VERSION 5.8 ;
BUSBITCHARS "[]" ;
DIVIDERCHAR "/" ;
UNITS
    DATABASE MICRONS 1000 ;
END UNITS

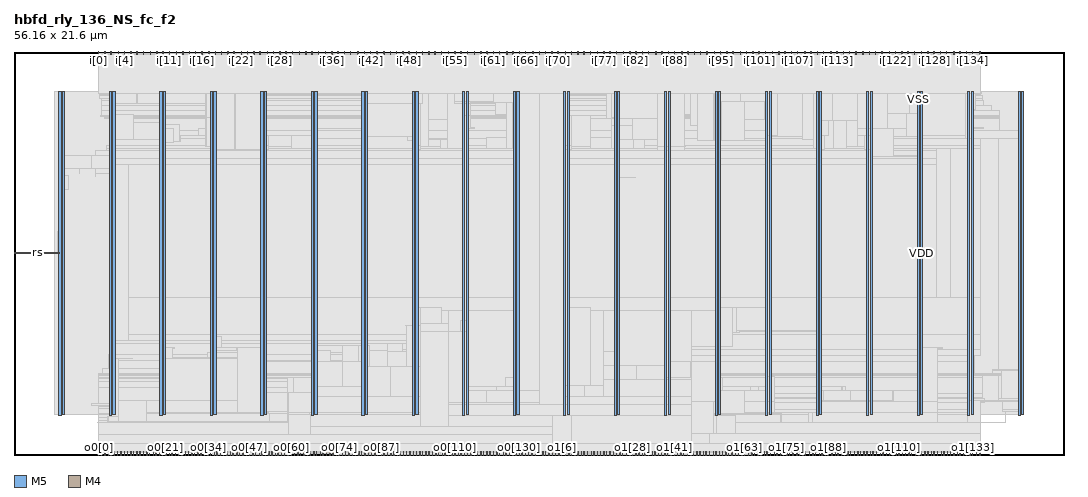
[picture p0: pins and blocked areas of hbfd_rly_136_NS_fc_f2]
MACRO hbfd_rly_136_NS_fc_f2
  FOREIGN hbfd_rly_136_NS_fc_f2 0 0 ;
  CLASS BLOCK ;
  SIZE 56.16 BY 21.6 ;
  PIN clk_in
    DIRECTION INPUT ;
    USE SIGNAL ;
    PORT
      LAYER M5 ;
        RECT  28.08 21.408 28.104 21.6 ;
    END
  END clk_in
  PIN clk_out0
    DIRECTION OUTPUT ;
    USE SIGNAL ;
    PORT
      LAYER M5 ;
        RECT  16.176 0 16.2 0.192 ;
    END
  END clk_out0
  PIN clk_out1
    DIRECTION OUTPUT ;
    USE SIGNAL ;
    PORT
      LAYER M5 ;
        RECT  39.936 0 39.96 0.192 ;
    END
  END clk_out1
  PIN i[0]
    DIRECTION INPUT ;
    USE SIGNAL ;
    PORT
      LAYER M5 ;
        RECT  4.512 21.408 4.536 21.6 ;
    END
  END i[0]
  PIN i[100]
    DIRECTION INPUT ;
    USE SIGNAL ;
    PORT
      LAYER M5 ;
        RECT  39.504 21.408 39.528 21.6 ;
    END
  END i[100]
  PIN i[101]
    DIRECTION INPUT ;
    USE SIGNAL ;
    PORT
      LAYER M5 ;
        RECT  39.84 21.408 39.864 21.6 ;
    END
  END i[101]
  PIN i[102]
    DIRECTION INPUT ;
    USE SIGNAL ;
    PORT
      LAYER M5 ;
        RECT  40.176 21.408 40.2 21.6 ;
    END
  END i[102]
  PIN i[103]
    DIRECTION INPUT ;
    USE SIGNAL ;
    PORT
      LAYER M5 ;
        RECT  40.56 21.408 40.584 21.6 ;
    END
  END i[103]
  PIN i[104]
    DIRECTION INPUT ;
    USE SIGNAL ;
    PORT
      LAYER M5 ;
        RECT  40.896 21.408 40.92 21.6 ;
    END
  END i[104]
  PIN i[105]
    DIRECTION INPUT ;
    USE SIGNAL ;
    PORT
      LAYER M5 ;
        RECT  41.232 21.408 41.256 21.6 ;
    END
  END i[105]
  PIN i[106]
    DIRECTION INPUT ;
    USE SIGNAL ;
    PORT
      LAYER M5 ;
        RECT  41.568 21.408 41.592 21.6 ;
    END
  END i[106]
  PIN i[107]
    DIRECTION INPUT ;
    USE SIGNAL ;
    PORT
      LAYER M5 ;
        RECT  41.904 21.408 41.928 21.6 ;
    END
  END i[107]
  PIN i[108]
    DIRECTION INPUT ;
    USE SIGNAL ;
    PORT
      LAYER M5 ;
        RECT  42.288 21.408 42.312 21.6 ;
    END
  END i[108]
  PIN i[109]
    DIRECTION INPUT ;
    USE SIGNAL ;
    PORT
      LAYER M5 ;
        RECT  42.624 21.408 42.648 21.6 ;
    END
  END i[109]
  PIN i[10]
    DIRECTION INPUT ;
    USE SIGNAL ;
    PORT
      LAYER M5 ;
        RECT  7.968 21.408 7.992 21.6 ;
    END
  END i[10]
  PIN i[110]
    DIRECTION INPUT ;
    USE SIGNAL ;
    PORT
      LAYER M5 ;
        RECT  42.96 21.408 42.984 21.6 ;
    END
  END i[110]
  PIN i[111]
    DIRECTION INPUT ;
    USE SIGNAL ;
    PORT
      LAYER M5 ;
        RECT  43.296 21.408 43.32 21.6 ;
    END
  END i[111]
  PIN i[112]
    DIRECTION INPUT ;
    USE SIGNAL ;
    PORT
      LAYER M5 ;
        RECT  43.68 21.408 43.704 21.6 ;
    END
  END i[112]
  PIN i[113]
    DIRECTION INPUT ;
    USE SIGNAL ;
    PORT
      LAYER M5 ;
        RECT  44.016 21.408 44.04 21.6 ;
    END
  END i[113]
  PIN i[114]
    DIRECTION INPUT ;
    USE SIGNAL ;
    PORT
      LAYER M5 ;
        RECT  44.352 21.408 44.376 21.6 ;
    END
  END i[114]
  PIN i[115]
    DIRECTION INPUT ;
    USE SIGNAL ;
    PORT
      LAYER M5 ;
        RECT  44.688 21.408 44.712 21.6 ;
    END
  END i[115]
  PIN i[116]
    DIRECTION INPUT ;
    USE SIGNAL ;
    PORT
      LAYER M5 ;
        RECT  45.024 21.408 45.048 21.6 ;
    END
  END i[116]
  PIN i[117]
    DIRECTION INPUT ;
    USE SIGNAL ;
    PORT
      LAYER M5 ;
        RECT  45.408 21.408 45.432 21.6 ;
    END
  END i[117]
  PIN i[118]
    DIRECTION INPUT ;
    USE SIGNAL ;
    PORT
      LAYER M5 ;
        RECT  45.744 21.408 45.768 21.6 ;
    END
  END i[118]
  PIN i[119]
    DIRECTION INPUT ;
    USE SIGNAL ;
    PORT
      LAYER M5 ;
        RECT  46.08 21.408 46.104 21.6 ;
    END
  END i[119]
  PIN i[11]
    DIRECTION INPUT ;
    USE SIGNAL ;
    PORT
      LAYER M5 ;
        RECT  8.304 21.408 8.328 21.6 ;
    END
  END i[11]
  PIN i[120]
    DIRECTION INPUT ;
    USE SIGNAL ;
    PORT
      LAYER M5 ;
        RECT  46.416 21.408 46.44 21.6 ;
    END
  END i[120]
  PIN i[121]
    DIRECTION INPUT ;
    USE SIGNAL ;
    PORT
      LAYER M5 ;
        RECT  46.8 21.408 46.824 21.6 ;
    END
  END i[121]
  PIN i[122]
    DIRECTION INPUT ;
    USE SIGNAL ;
    PORT
      LAYER M5 ;
        RECT  47.136 21.408 47.16 21.6 ;
    END
  END i[122]
  PIN i[123]
    DIRECTION INPUT ;
    USE SIGNAL ;
    PORT
      LAYER M5 ;
        RECT  47.472 21.408 47.496 21.6 ;
    END
  END i[123]
  PIN i[124]
    DIRECTION INPUT ;
    USE SIGNAL ;
    PORT
      LAYER M5 ;
        RECT  47.808 21.408 47.832 21.6 ;
    END
  END i[124]
  PIN i[125]
    DIRECTION INPUT ;
    USE SIGNAL ;
    PORT
      LAYER M5 ;
        RECT  48.144 21.408 48.168 21.6 ;
    END
  END i[125]
  PIN i[126]
    DIRECTION INPUT ;
    USE SIGNAL ;
    PORT
      LAYER M5 ;
        RECT  48.528 21.408 48.552 21.6 ;
    END
  END i[126]
  PIN i[127]
    DIRECTION INPUT ;
    USE SIGNAL ;
    PORT
      LAYER M5 ;
        RECT  48.864 21.408 48.888 21.6 ;
    END
  END i[127]
  PIN i[128]
    DIRECTION INPUT ;
    USE SIGNAL ;
    PORT
      LAYER M5 ;
        RECT  49.2 21.408 49.224 21.6 ;
    END
  END i[128]
  PIN i[129]
    DIRECTION INPUT ;
    USE SIGNAL ;
    PORT
      LAYER M5 ;
        RECT  49.536 21.408 49.56 21.6 ;
    END
  END i[129]
  PIN i[12]
    DIRECTION INPUT ;
    USE SIGNAL ;
    PORT
      LAYER M5 ;
        RECT  8.688 21.408 8.712 21.6 ;
    END
  END i[12]
  PIN i[130]
    DIRECTION INPUT ;
    USE SIGNAL ;
    PORT
      LAYER M5 ;
        RECT  49.872 21.408 49.896 21.6 ;
    END
  END i[130]
  PIN i[131]
    DIRECTION INPUT ;
    USE SIGNAL ;
    PORT
      LAYER M5 ;
        RECT  50.256 21.408 50.28 21.6 ;
    END
  END i[131]
  PIN i[132]
    DIRECTION INPUT ;
    USE SIGNAL ;
    PORT
      LAYER M5 ;
        RECT  50.592 21.408 50.616 21.6 ;
    END
  END i[132]
  PIN i[133]
    DIRECTION INPUT ;
    USE SIGNAL ;
    PORT
      LAYER M5 ;
        RECT  50.928 21.408 50.952 21.6 ;
    END
  END i[133]
  PIN i[134]
    DIRECTION INPUT ;
    USE SIGNAL ;
    PORT
      LAYER M5 ;
        RECT  51.264 21.408 51.288 21.6 ;
    END
  END i[134]
  PIN i[135]
    DIRECTION INPUT ;
    USE SIGNAL ;
    PORT
      LAYER M5 ;
        RECT  51.648 21.408 51.672 21.6 ;
    END
  END i[135]
  PIN i[13]
    DIRECTION INPUT ;
    USE SIGNAL ;
    PORT
      LAYER M5 ;
        RECT  9.024 21.408 9.048 21.6 ;
    END
  END i[13]
  PIN i[14]
    DIRECTION INPUT ;
    USE SIGNAL ;
    PORT
      LAYER M5 ;
        RECT  9.36 21.408 9.384 21.6 ;
    END
  END i[14]
  PIN i[15]
    DIRECTION INPUT ;
    USE SIGNAL ;
    PORT
      LAYER M5 ;
        RECT  9.696 21.408 9.72 21.6 ;
    END
  END i[15]
  PIN i[16]
    DIRECTION INPUT ;
    USE SIGNAL ;
    PORT
      LAYER M5 ;
        RECT  10.032 21.408 10.056 21.6 ;
    END
  END i[16]
  PIN i[17]
    DIRECTION INPUT ;
    USE SIGNAL ;
    PORT
      LAYER M5 ;
        RECT  10.416 21.408 10.44 21.6 ;
    END
  END i[17]
  PIN i[18]
    DIRECTION INPUT ;
    USE SIGNAL ;
    PORT
      LAYER M5 ;
        RECT  10.752 21.408 10.776 21.6 ;
    END
  END i[18]
  PIN i[19]
    DIRECTION INPUT ;
    USE SIGNAL ;
    PORT
      LAYER M5 ;
        RECT  11.088 21.408 11.112 21.6 ;
    END
  END i[19]
  PIN i[1]
    DIRECTION INPUT ;
    USE SIGNAL ;
    PORT
      LAYER M5 ;
        RECT  4.848 21.408 4.872 21.6 ;
    END
  END i[1]
  PIN i[20]
    DIRECTION INPUT ;
    USE SIGNAL ;
    PORT
      LAYER M5 ;
        RECT  11.424 21.408 11.448 21.6 ;
    END
  END i[20]
  PIN i[21]
    DIRECTION INPUT ;
    USE SIGNAL ;
    PORT
      LAYER M5 ;
        RECT  11.76 21.408 11.784 21.6 ;
    END
  END i[21]
  PIN i[22]
    DIRECTION INPUT ;
    USE SIGNAL ;
    PORT
      LAYER M5 ;
        RECT  12.144 21.408 12.168 21.6 ;
    END
  END i[22]
  PIN i[23]
    DIRECTION INPUT ;
    USE SIGNAL ;
    PORT
      LAYER M5 ;
        RECT  12.48 21.408 12.504 21.6 ;
    END
  END i[23]
  PIN i[24]
    DIRECTION INPUT ;
    USE SIGNAL ;
    PORT
      LAYER M5 ;
        RECT  12.816 21.408 12.84 21.6 ;
    END
  END i[24]
  PIN i[25]
    DIRECTION INPUT ;
    USE SIGNAL ;
    PORT
      LAYER M5 ;
        RECT  13.152 21.408 13.176 21.6 ;
    END
  END i[25]
  PIN i[26]
    DIRECTION INPUT ;
    USE SIGNAL ;
    PORT
      LAYER M5 ;
        RECT  13.536 21.408 13.56 21.6 ;
    END
  END i[26]
  PIN i[27]
    DIRECTION INPUT ;
    USE SIGNAL ;
    PORT
      LAYER M5 ;
        RECT  13.872 21.408 13.896 21.6 ;
    END
  END i[27]
  PIN i[28]
    DIRECTION INPUT ;
    USE SIGNAL ;
    PORT
      LAYER M5 ;
        RECT  14.208 21.408 14.232 21.6 ;
    END
  END i[28]
  PIN i[29]
    DIRECTION INPUT ;
    USE SIGNAL ;
    PORT
      LAYER M5 ;
        RECT  14.544 21.408 14.568 21.6 ;
    END
  END i[29]
  PIN i[2]
    DIRECTION INPUT ;
    USE SIGNAL ;
    PORT
      LAYER M5 ;
        RECT  5.184 21.408 5.208 21.6 ;
    END
  END i[2]
  PIN i[30]
    DIRECTION INPUT ;
    USE SIGNAL ;
    PORT
      LAYER M5 ;
        RECT  14.88 21.408 14.904 21.6 ;
    END
  END i[30]
  PIN i[31]
    DIRECTION INPUT ;
    USE SIGNAL ;
    PORT
      LAYER M5 ;
        RECT  15.264 21.408 15.288 21.6 ;
    END
  END i[31]
  PIN i[32]
    DIRECTION INPUT ;
    USE SIGNAL ;
    PORT
      LAYER M5 ;
        RECT  15.6 21.408 15.624 21.6 ;
    END
  END i[32]
  PIN i[33]
    DIRECTION INPUT ;
    USE SIGNAL ;
    PORT
      LAYER M5 ;
        RECT  15.936 21.408 15.96 21.6 ;
    END
  END i[33]
  PIN i[34]
    DIRECTION INPUT ;
    USE SIGNAL ;
    PORT
      LAYER M5 ;
        RECT  16.272 21.408 16.296 21.6 ;
    END
  END i[34]
  PIN i[35]
    DIRECTION INPUT ;
    USE SIGNAL ;
    PORT
      LAYER M5 ;
        RECT  16.656 21.408 16.68 21.6 ;
    END
  END i[35]
  PIN i[36]
    DIRECTION INPUT ;
    USE SIGNAL ;
    PORT
      LAYER M5 ;
        RECT  16.992 21.408 17.016 21.6 ;
    END
  END i[36]
  PIN i[37]
    DIRECTION INPUT ;
    USE SIGNAL ;
    PORT
      LAYER M5 ;
        RECT  17.328 21.408 17.352 21.6 ;
    END
  END i[37]
  PIN i[38]
    DIRECTION INPUT ;
    USE SIGNAL ;
    PORT
      LAYER M5 ;
        RECT  17.664 21.408 17.688 21.6 ;
    END
  END i[38]
  PIN i[39]
    DIRECTION INPUT ;
    USE SIGNAL ;
    PORT
      LAYER M5 ;
        RECT  18 21.408 18.024 21.6 ;
    END
  END i[39]
  PIN i[3]
    DIRECTION INPUT ;
    USE SIGNAL ;
    PORT
      LAYER M5 ;
        RECT  5.568 21.408 5.592 21.6 ;
    END
  END i[3]
  PIN i[40]
    DIRECTION INPUT ;
    USE SIGNAL ;
    PORT
      LAYER M5 ;
        RECT  18.384 21.408 18.408 21.6 ;
    END
  END i[40]
  PIN i[41]
    DIRECTION INPUT ;
    USE SIGNAL ;
    PORT
      LAYER M5 ;
        RECT  18.72 21.408 18.744 21.6 ;
    END
  END i[41]
  PIN i[42]
    DIRECTION INPUT ;
    USE SIGNAL ;
    PORT
      LAYER M5 ;
        RECT  19.056 21.408 19.08 21.6 ;
    END
  END i[42]
  PIN i[43]
    DIRECTION INPUT ;
    USE SIGNAL ;
    PORT
      LAYER M5 ;
        RECT  19.392 21.408 19.416 21.6 ;
    END
  END i[43]
  PIN i[44]
    DIRECTION INPUT ;
    USE SIGNAL ;
    PORT
      LAYER M5 ;
        RECT  19.776 21.408 19.8 21.6 ;
    END
  END i[44]
  PIN i[45]
    DIRECTION INPUT ;
    USE SIGNAL ;
    PORT
      LAYER M5 ;
        RECT  20.112 21.408 20.136 21.6 ;
    END
  END i[45]
  PIN i[46]
    DIRECTION INPUT ;
    USE SIGNAL ;
    PORT
      LAYER M5 ;
        RECT  20.448 21.408 20.472 21.6 ;
    END
  END i[46]
  PIN i[47]
    DIRECTION INPUT ;
    USE SIGNAL ;
    PORT
      LAYER M5 ;
        RECT  20.784 21.408 20.808 21.6 ;
    END
  END i[47]
  PIN i[48]
    DIRECTION INPUT ;
    USE SIGNAL ;
    PORT
      LAYER M5 ;
        RECT  21.12 21.408 21.144 21.6 ;
    END
  END i[48]
  PIN i[49]
    DIRECTION INPUT ;
    USE SIGNAL ;
    PORT
      LAYER M5 ;
        RECT  21.504 21.408 21.528 21.6 ;
    END
  END i[49]
  PIN i[4]
    DIRECTION INPUT ;
    USE SIGNAL ;
    PORT
      LAYER M5 ;
        RECT  5.904 21.408 5.928 21.6 ;
    END
  END i[4]
  PIN i[50]
    DIRECTION INPUT ;
    USE SIGNAL ;
    PORT
      LAYER M5 ;
        RECT  21.84 21.408 21.864 21.6 ;
    END
  END i[50]
  PIN i[51]
    DIRECTION INPUT ;
    USE SIGNAL ;
    PORT
      LAYER M5 ;
        RECT  22.176 21.408 22.2 21.6 ;
    END
  END i[51]
  PIN i[52]
    DIRECTION INPUT ;
    USE SIGNAL ;
    PORT
      LAYER M5 ;
        RECT  22.512 21.408 22.536 21.6 ;
    END
  END i[52]
  PIN i[53]
    DIRECTION INPUT ;
    USE SIGNAL ;
    PORT
      LAYER M5 ;
        RECT  22.848 21.408 22.872 21.6 ;
    END
  END i[53]
  PIN i[54]
    DIRECTION INPUT ;
    USE SIGNAL ;
    PORT
      LAYER M5 ;
        RECT  23.232 21.408 23.256 21.6 ;
    END
  END i[54]
  PIN i[55]
    DIRECTION INPUT ;
    USE SIGNAL ;
    PORT
      LAYER M5 ;
        RECT  23.568 21.408 23.592 21.6 ;
    END
  END i[55]
  PIN i[56]
    DIRECTION INPUT ;
    USE SIGNAL ;
    PORT
      LAYER M5 ;
        RECT  23.904 21.408 23.928 21.6 ;
    END
  END i[56]
  PIN i[57]
    DIRECTION INPUT ;
    USE SIGNAL ;
    PORT
      LAYER M5 ;
        RECT  24.24 21.408 24.264 21.6 ;
    END
  END i[57]
  PIN i[58]
    DIRECTION INPUT ;
    USE SIGNAL ;
    PORT
      LAYER M5 ;
        RECT  24.624 21.408 24.648 21.6 ;
    END
  END i[58]
  PIN i[59]
    DIRECTION INPUT ;
    USE SIGNAL ;
    PORT
      LAYER M5 ;
        RECT  24.96 21.408 24.984 21.6 ;
    END
  END i[59]
  PIN i[5]
    DIRECTION INPUT ;
    USE SIGNAL ;
    PORT
      LAYER M5 ;
        RECT  6.24 21.408 6.264 21.6 ;
    END
  END i[5]
  PIN i[60]
    DIRECTION INPUT ;
    USE SIGNAL ;
    PORT
      LAYER M5 ;
        RECT  25.296 21.408 25.32 21.6 ;
    END
  END i[60]
  PIN i[61]
    DIRECTION INPUT ;
    USE SIGNAL ;
    PORT
      LAYER M5 ;
        RECT  25.632 21.408 25.656 21.6 ;
    END
  END i[61]
  PIN i[62]
    DIRECTION INPUT ;
    USE SIGNAL ;
    PORT
      LAYER M5 ;
        RECT  25.968 21.408 25.992 21.6 ;
    END
  END i[62]
  PIN i[63]
    DIRECTION INPUT ;
    USE SIGNAL ;
    PORT
      LAYER M5 ;
        RECT  26.352 21.408 26.376 21.6 ;
    END
  END i[63]
  PIN i[64]
    DIRECTION INPUT ;
    USE SIGNAL ;
    PORT
      LAYER M5 ;
        RECT  26.688 21.408 26.712 21.6 ;
    END
  END i[64]
  PIN i[65]
    DIRECTION INPUT ;
    USE SIGNAL ;
    PORT
      LAYER M5 ;
        RECT  27.024 21.408 27.048 21.6 ;
    END
  END i[65]
  PIN i[66]
    DIRECTION INPUT ;
    USE SIGNAL ;
    PORT
      LAYER M5 ;
        RECT  27.36 21.408 27.384 21.6 ;
    END
  END i[66]
  PIN i[67]
    DIRECTION INPUT ;
    USE SIGNAL ;
    PORT
      LAYER M5 ;
        RECT  27.744 21.408 27.768 21.6 ;
    END
  END i[67]
  PIN i[68]
    DIRECTION INPUT ;
    USE SIGNAL ;
    PORT
      LAYER M5 ;
        RECT  28.416 21.408 28.44 21.6 ;
    END
  END i[68]
  PIN i[69]
    DIRECTION INPUT ;
    USE SIGNAL ;
    PORT
      LAYER M5 ;
        RECT  28.752 21.408 28.776 21.6 ;
    END
  END i[69]
  PIN i[6]
    DIRECTION INPUT ;
    USE SIGNAL ;
    PORT
      LAYER M5 ;
        RECT  6.576 21.408 6.6 21.6 ;
    END
  END i[6]
  PIN i[70]
    DIRECTION INPUT ;
    USE SIGNAL ;
    PORT
      LAYER M5 ;
        RECT  29.088 21.408 29.112 21.6 ;
    END
  END i[70]
  PIN i[71]
    DIRECTION INPUT ;
    USE SIGNAL ;
    PORT
      LAYER M5 ;
        RECT  29.472 21.408 29.496 21.6 ;
    END
  END i[71]
  PIN i[72]
    DIRECTION INPUT ;
    USE SIGNAL ;
    PORT
      LAYER M5 ;
        RECT  29.808 21.408 29.832 21.6 ;
    END
  END i[72]
  PIN i[73]
    DIRECTION INPUT ;
    USE SIGNAL ;
    PORT
      LAYER M5 ;
        RECT  30.144 21.408 30.168 21.6 ;
    END
  END i[73]
  PIN i[74]
    DIRECTION INPUT ;
    USE SIGNAL ;
    PORT
      LAYER M5 ;
        RECT  30.48 21.408 30.504 21.6 ;
    END
  END i[74]
  PIN i[75]
    DIRECTION INPUT ;
    USE SIGNAL ;
    PORT
      LAYER M5 ;
        RECT  30.816 21.408 30.84 21.6 ;
    END
  END i[75]
  PIN i[76]
    DIRECTION INPUT ;
    USE SIGNAL ;
    PORT
      LAYER M5 ;
        RECT  31.2 21.408 31.224 21.6 ;
    END
  END i[76]
  PIN i[77]
    DIRECTION INPUT ;
    USE SIGNAL ;
    PORT
      LAYER M5 ;
        RECT  31.536 21.408 31.56 21.6 ;
    END
  END i[77]
  PIN i[78]
    DIRECTION INPUT ;
    USE SIGNAL ;
    PORT
      LAYER M5 ;
        RECT  31.872 21.408 31.896 21.6 ;
    END
  END i[78]
  PIN i[79]
    DIRECTION INPUT ;
    USE SIGNAL ;
    PORT
      LAYER M5 ;
        RECT  32.208 21.408 32.232 21.6 ;
    END
  END i[79]
  PIN i[7]
    DIRECTION INPUT ;
    USE SIGNAL ;
    PORT
      LAYER M5 ;
        RECT  6.912 21.408 6.936 21.6 ;
    END
  END i[7]
  PIN i[80]
    DIRECTION INPUT ;
    USE SIGNAL ;
    PORT
      LAYER M5 ;
        RECT  32.592 21.408 32.616 21.6 ;
    END
  END i[80]
  PIN i[81]
    DIRECTION INPUT ;
    USE SIGNAL ;
    PORT
      LAYER M5 ;
        RECT  32.928 21.408 32.952 21.6 ;
    END
  END i[81]
  PIN i[82]
    DIRECTION INPUT ;
    USE SIGNAL ;
    PORT
      LAYER M5 ;
        RECT  33.264 21.408 33.288 21.6 ;
    END
  END i[82]
  PIN i[83]
    DIRECTION INPUT ;
    USE SIGNAL ;
    PORT
      LAYER M5 ;
        RECT  33.6 21.408 33.624 21.6 ;
    END
  END i[83]
  PIN i[84]
    DIRECTION INPUT ;
    USE SIGNAL ;
    PORT
      LAYER M5 ;
        RECT  33.936 21.408 33.96 21.6 ;
    END
  END i[84]
  PIN i[85]
    DIRECTION INPUT ;
    USE SIGNAL ;
    PORT
      LAYER M5 ;
        RECT  34.32 21.408 34.344 21.6 ;
    END
  END i[85]
  PIN i[86]
    DIRECTION INPUT ;
    USE SIGNAL ;
    PORT
      LAYER M5 ;
        RECT  34.656 21.408 34.68 21.6 ;
    END
  END i[86]
  PIN i[87]
    DIRECTION INPUT ;
    USE SIGNAL ;
    PORT
      LAYER M5 ;
        RECT  34.992 21.408 35.016 21.6 ;
    END
  END i[87]
  PIN i[88]
    DIRECTION INPUT ;
    USE SIGNAL ;
    PORT
      LAYER M5 ;
        RECT  35.328 21.408 35.352 21.6 ;
    END
  END i[88]
  PIN i[89]
    DIRECTION INPUT ;
    USE SIGNAL ;
    PORT
      LAYER M5 ;
        RECT  35.712 21.408 35.736 21.6 ;
    END
  END i[89]
  PIN i[8]
    DIRECTION INPUT ;
    USE SIGNAL ;
    PORT
      LAYER M5 ;
        RECT  7.296 21.408 7.32 21.6 ;
    END
  END i[8]
  PIN i[90]
    DIRECTION INPUT ;
    USE SIGNAL ;
    PORT
      LAYER M5 ;
        RECT  36.048 21.408 36.072 21.6 ;
    END
  END i[90]
  PIN i[91]
    DIRECTION INPUT ;
    USE SIGNAL ;
    PORT
      LAYER M5 ;
        RECT  36.384 21.408 36.408 21.6 ;
    END
  END i[91]
  PIN i[92]
    DIRECTION INPUT ;
    USE SIGNAL ;
    PORT
      LAYER M5 ;
        RECT  36.72 21.408 36.744 21.6 ;
    END
  END i[92]
  PIN i[93]
    DIRECTION INPUT ;
    USE SIGNAL ;
    PORT
      LAYER M5 ;
        RECT  37.056 21.408 37.08 21.6 ;
    END
  END i[93]
  PIN i[94]
    DIRECTION INPUT ;
    USE SIGNAL ;
    PORT
      LAYER M5 ;
        RECT  37.44 21.408 37.464 21.6 ;
    END
  END i[94]
  PIN i[95]
    DIRECTION INPUT ;
    USE SIGNAL ;
    PORT
      LAYER M5 ;
        RECT  37.776 21.408 37.8 21.6 ;
    END
  END i[95]
  PIN i[96]
    DIRECTION INPUT ;
    USE SIGNAL ;
    PORT
      LAYER M5 ;
        RECT  38.112 21.408 38.136 21.6 ;
    END
  END i[96]
  PIN i[97]
    DIRECTION INPUT ;
    USE SIGNAL ;
    PORT
      LAYER M5 ;
        RECT  38.448 21.408 38.472 21.6 ;
    END
  END i[97]
  PIN i[98]
    DIRECTION INPUT ;
    USE SIGNAL ;
    PORT
      LAYER M5 ;
        RECT  38.832 21.408 38.856 21.6 ;
    END
  END i[98]
  PIN i[99]
    DIRECTION INPUT ;
    USE SIGNAL ;
    PORT
      LAYER M5 ;
        RECT  39.168 21.408 39.192 21.6 ;
    END
  END i[99]
  PIN i[9]
    DIRECTION INPUT ;
    USE SIGNAL ;
    PORT
      LAYER M5 ;
        RECT  7.632 21.408 7.656 21.6 ;
    END
  END i[9]
  PIN o0[0]
    DIRECTION OUTPUT ;
    USE SIGNAL ;
    PORT
      LAYER M5 ;
        RECT  4.512 0 4.536 0.192 ;
    END
  END o0[0]
  PIN o0[100]
    DIRECTION OUTPUT ;
    USE SIGNAL ;
    PORT
      LAYER M5 ;
        RECT  21.84 0 21.864 0.192 ;
    END
  END o0[100]
  PIN o0[101]
    DIRECTION OUTPUT ;
    USE SIGNAL ;
    PORT
      LAYER M5 ;
        RECT  22.032 0 22.056 0.192 ;
    END
  END o0[101]
  PIN o0[102]
    DIRECTION OUTPUT ;
    USE SIGNAL ;
    PORT
      LAYER M5 ;
        RECT  22.176 0 22.2 0.192 ;
    END
  END o0[102]
  PIN o0[103]
    DIRECTION OUTPUT ;
    USE SIGNAL ;
    PORT
      LAYER M5 ;
        RECT  22.368 0 22.392 0.192 ;
    END
  END o0[103]
  PIN o0[104]
    DIRECTION OUTPUT ;
    USE SIGNAL ;
    PORT
      LAYER M5 ;
        RECT  22.56 0 22.584 0.192 ;
    END
  END o0[104]
  PIN o0[105]
    DIRECTION OUTPUT ;
    USE SIGNAL ;
    PORT
      LAYER M5 ;
        RECT  22.704 0 22.728 0.192 ;
    END
  END o0[105]
  PIN o0[106]
    DIRECTION OUTPUT ;
    USE SIGNAL ;
    PORT
      LAYER M5 ;
        RECT  22.896 0 22.92 0.192 ;
    END
  END o0[106]
  PIN o0[107]
    DIRECTION OUTPUT ;
    USE SIGNAL ;
    PORT
      LAYER M5 ;
        RECT  23.04 0 23.064 0.192 ;
    END
  END o0[107]
  PIN o0[108]
    DIRECTION OUTPUT ;
    USE SIGNAL ;
    PORT
      LAYER M5 ;
        RECT  23.232 0 23.256 0.192 ;
    END
  END o0[108]
  PIN o0[109]
    DIRECTION OUTPUT ;
    USE SIGNAL ;
    PORT
      LAYER M5 ;
        RECT  23.424 0 23.448 0.192 ;
    END
  END o0[109]
  PIN o0[10]
    DIRECTION OUTPUT ;
    USE SIGNAL ;
    PORT
      LAYER M5 ;
        RECT  6.24 0 6.264 0.192 ;
    END
  END o0[10]
  PIN o0[110]
    DIRECTION OUTPUT ;
    USE SIGNAL ;
    PORT
      LAYER M5 ;
        RECT  23.568 0 23.592 0.192 ;
    END
  END o0[110]
  PIN o0[111]
    DIRECTION OUTPUT ;
    USE SIGNAL ;
    PORT
      LAYER M5 ;
        RECT  23.76 0 23.784 0.192 ;
    END
  END o0[111]
  PIN o0[112]
    DIRECTION OUTPUT ;
    USE SIGNAL ;
    PORT
      LAYER M5 ;
        RECT  23.904 0 23.928 0.192 ;
    END
  END o0[112]
  PIN o0[113]
    DIRECTION OUTPUT ;
    USE SIGNAL ;
    PORT
      LAYER M5 ;
        RECT  24.096 0 24.12 0.192 ;
    END
  END o0[113]
  PIN o0[114]
    DIRECTION OUTPUT ;
    USE SIGNAL ;
    PORT
      LAYER M5 ;
        RECT  24.24 0 24.264 0.192 ;
    END
  END o0[114]
  PIN o0[115]
    DIRECTION OUTPUT ;
    USE SIGNAL ;
    PORT
      LAYER M5 ;
        RECT  24.432 0 24.456 0.192 ;
    END
  END o0[115]
  PIN o0[116]
    DIRECTION OUTPUT ;
    USE SIGNAL ;
    PORT
      LAYER M5 ;
        RECT  24.624 0 24.648 0.192 ;
    END
  END o0[116]
  PIN o0[117]
    DIRECTION OUTPUT ;
    USE SIGNAL ;
    PORT
      LAYER M5 ;
        RECT  24.768 0 24.792 0.192 ;
    END
  END o0[117]
  PIN o0[118]
    DIRECTION OUTPUT ;
    USE SIGNAL ;
    PORT
      LAYER M5 ;
        RECT  24.96 0 24.984 0.192 ;
    END
  END o0[118]
  PIN o0[119]
    DIRECTION OUTPUT ;
    USE SIGNAL ;
    PORT
      LAYER M5 ;
        RECT  25.104 0 25.128 0.192 ;
    END
  END o0[119]
  PIN o0[11]
    DIRECTION OUTPUT ;
    USE SIGNAL ;
    PORT
      LAYER M5 ;
        RECT  6.384 0 6.408 0.192 ;
    END
  END o0[11]
  PIN o0[120]
    DIRECTION OUTPUT ;
    USE SIGNAL ;
    PORT
      LAYER M5 ;
        RECT  25.296 0 25.32 0.192 ;
    END
  END o0[120]
  PIN o0[121]
    DIRECTION OUTPUT ;
    USE SIGNAL ;
    PORT
      LAYER M5 ;
        RECT  25.44 0 25.464 0.192 ;
    END
  END o0[121]
  PIN o0[122]
    DIRECTION OUTPUT ;
    USE SIGNAL ;
    PORT
      LAYER M5 ;
        RECT  25.632 0 25.656 0.192 ;
    END
  END o0[122]
  PIN o0[123]
    DIRECTION OUTPUT ;
    USE SIGNAL ;
    PORT
      LAYER M5 ;
        RECT  25.824 0 25.848 0.192 ;
    END
  END o0[123]
  PIN o0[124]
    DIRECTION OUTPUT ;
    USE SIGNAL ;
    PORT
      LAYER M5 ;
        RECT  25.968 0 25.992 0.192 ;
    END
  END o0[124]
  PIN o0[125]
    DIRECTION OUTPUT ;
    USE SIGNAL ;
    PORT
      LAYER M5 ;
        RECT  26.16 0 26.184 0.192 ;
    END
  END o0[125]
  PIN o0[126]
    DIRECTION OUTPUT ;
    USE SIGNAL ;
    PORT
      LAYER M5 ;
        RECT  26.304 0 26.328 0.192 ;
    END
  END o0[126]
  PIN o0[127]
    DIRECTION OUTPUT ;
    USE SIGNAL ;
    PORT
      LAYER M5 ;
        RECT  26.496 0 26.52 0.192 ;
    END
  END o0[127]
  PIN o0[128]
    DIRECTION OUTPUT ;
    USE SIGNAL ;
    PORT
      LAYER M5 ;
        RECT  26.688 0 26.712 0.192 ;
    END
  END o0[128]
  PIN o0[129]
    DIRECTION OUTPUT ;
    USE SIGNAL ;
    PORT
      LAYER M5 ;
        RECT  26.832 0 26.856 0.192 ;
    END
  END o0[129]
  PIN o0[12]
    DIRECTION OUTPUT ;
    USE SIGNAL ;
    PORT
      LAYER M5 ;
        RECT  6.576 0 6.6 0.192 ;
    END
  END o0[12]
  PIN o0[130]
    DIRECTION OUTPUT ;
    USE SIGNAL ;
    PORT
      LAYER M5 ;
        RECT  27.024 0 27.048 0.192 ;
    END
  END o0[130]
  PIN o0[131]
    DIRECTION OUTPUT ;
    USE SIGNAL ;
    PORT
      LAYER M5 ;
        RECT  27.168 0 27.192 0.192 ;
    END
  END o0[131]
  PIN o0[132]
    DIRECTION OUTPUT ;
    USE SIGNAL ;
    PORT
      LAYER M5 ;
        RECT  27.36 0 27.384 0.192 ;
    END
  END o0[132]
  PIN o0[133]
    DIRECTION OUTPUT ;
    USE SIGNAL ;
    PORT
      LAYER M5 ;
        RECT  27.504 0 27.528 0.192 ;
    END
  END o0[133]
  PIN o0[134]
    DIRECTION OUTPUT ;
    USE SIGNAL ;
    PORT
      LAYER M5 ;
        RECT  27.696 0 27.72 0.192 ;
    END
  END o0[134]
  PIN o0[135]
    DIRECTION OUTPUT ;
    USE SIGNAL ;
    PORT
      LAYER M5 ;
        RECT  27.888 0 27.912 0.192 ;
    END
  END o0[135]
  PIN o0[13]
    DIRECTION OUTPUT ;
    USE SIGNAL ;
    PORT
      LAYER M5 ;
        RECT  6.72 0 6.744 0.192 ;
    END
  END o0[13]
  PIN o0[14]
    DIRECTION OUTPUT ;
    USE SIGNAL ;
    PORT
      LAYER M5 ;
        RECT  6.912 0 6.936 0.192 ;
    END
  END o0[14]
  PIN o0[15]
    DIRECTION OUTPUT ;
    USE SIGNAL ;
    PORT
      LAYER M5 ;
        RECT  7.104 0 7.128 0.192 ;
    END
  END o0[15]
  PIN o0[16]
    DIRECTION OUTPUT ;
    USE SIGNAL ;
    PORT
      LAYER M5 ;
        RECT  7.248 0 7.272 0.192 ;
    END
  END o0[16]
  PIN o0[17]
    DIRECTION OUTPUT ;
    USE SIGNAL ;
    PORT
      LAYER M5 ;
        RECT  7.44 0 7.464 0.192 ;
    END
  END o0[17]
  PIN o0[18]
    DIRECTION OUTPUT ;
    USE SIGNAL ;
    PORT
      LAYER M5 ;
        RECT  7.584 0 7.608 0.192 ;
    END
  END o0[18]
  PIN o0[19]
    DIRECTION OUTPUT ;
    USE SIGNAL ;
    PORT
      LAYER M5 ;
        RECT  7.776 0 7.8 0.192 ;
    END
  END o0[19]
  PIN o0[1]
    DIRECTION OUTPUT ;
    USE SIGNAL ;
    PORT
      LAYER M5 ;
        RECT  4.656 0 4.68 0.192 ;
    END
  END o0[1]
  PIN o0[20]
    DIRECTION OUTPUT ;
    USE SIGNAL ;
    PORT
      LAYER M5 ;
        RECT  7.92 0 7.944 0.192 ;
    END
  END o0[20]
  PIN o0[21]
    DIRECTION OUTPUT ;
    USE SIGNAL ;
    PORT
      LAYER M5 ;
        RECT  8.112 0 8.136 0.192 ;
    END
  END o0[21]
  PIN o0[22]
    DIRECTION OUTPUT ;
    USE SIGNAL ;
    PORT
      LAYER M5 ;
        RECT  8.304 0 8.328 0.192 ;
    END
  END o0[22]
  PIN o0[23]
    DIRECTION OUTPUT ;
    USE SIGNAL ;
    PORT
      LAYER M5 ;
        RECT  8.448 0 8.472 0.192 ;
    END
  END o0[23]
  PIN o0[24]
    DIRECTION OUTPUT ;
    USE SIGNAL ;
    PORT
      LAYER M5 ;
        RECT  8.64 0 8.664 0.192 ;
    END
  END o0[24]
  PIN o0[25]
    DIRECTION OUTPUT ;
    USE SIGNAL ;
    PORT
      LAYER M5 ;
        RECT  8.784 0 8.808 0.192 ;
    END
  END o0[25]
  PIN o0[26]
    DIRECTION OUTPUT ;
    USE SIGNAL ;
    PORT
      LAYER M5 ;
        RECT  8.976 0 9 0.192 ;
    END
  END o0[26]
  PIN o0[27]
    DIRECTION OUTPUT ;
    USE SIGNAL ;
    PORT
      LAYER M5 ;
        RECT  9.168 0 9.192 0.192 ;
    END
  END o0[27]
  PIN o0[28]
    DIRECTION OUTPUT ;
    USE SIGNAL ;
    PORT
      LAYER M5 ;
        RECT  9.312 0 9.336 0.192 ;
    END
  END o0[28]
  PIN o0[29]
    DIRECTION OUTPUT ;
    USE SIGNAL ;
    PORT
      LAYER M5 ;
        RECT  9.504 0 9.528 0.192 ;
    END
  END o0[29]
  PIN o0[2]
    DIRECTION OUTPUT ;
    USE SIGNAL ;
    PORT
      LAYER M5 ;
        RECT  4.848 0 4.872 0.192 ;
    END
  END o0[2]
  PIN o0[30]
    DIRECTION OUTPUT ;
    USE SIGNAL ;
    PORT
      LAYER M5 ;
        RECT  9.648 0 9.672 0.192 ;
    END
  END o0[30]
  PIN o0[31]
    DIRECTION OUTPUT ;
    USE SIGNAL ;
    PORT
      LAYER M5 ;
        RECT  9.84 0 9.864 0.192 ;
    END
  END o0[31]
  PIN o0[32]
    DIRECTION OUTPUT ;
    USE SIGNAL ;
    PORT
      LAYER M5 ;
        RECT  9.984 0 10.008 0.192 ;
    END
  END o0[32]
  PIN o0[33]
    DIRECTION OUTPUT ;
    USE SIGNAL ;
    PORT
      LAYER M5 ;
        RECT  10.176 0 10.2 0.192 ;
    END
  END o0[33]
  PIN o0[34]
    DIRECTION OUTPUT ;
    USE SIGNAL ;
    PORT
      LAYER M5 ;
        RECT  10.368 0 10.392 0.192 ;
    END
  END o0[34]
  PIN o0[35]
    DIRECTION OUTPUT ;
    USE SIGNAL ;
    PORT
      LAYER M5 ;
        RECT  10.512 0 10.536 0.192 ;
    END
  END o0[35]
  PIN o0[36]
    DIRECTION OUTPUT ;
    USE SIGNAL ;
    PORT
      LAYER M5 ;
        RECT  10.704 0 10.728 0.192 ;
    END
  END o0[36]
  PIN o0[37]
    DIRECTION OUTPUT ;
    USE SIGNAL ;
    PORT
      LAYER M5 ;
        RECT  10.848 0 10.872 0.192 ;
    END
  END o0[37]
  PIN o0[38]
    DIRECTION OUTPUT ;
    USE SIGNAL ;
    PORT
      LAYER M5 ;
        RECT  11.04 0 11.064 0.192 ;
    END
  END o0[38]
  PIN o0[39]
    DIRECTION OUTPUT ;
    USE SIGNAL ;
    PORT
      LAYER M5 ;
        RECT  11.184 0 11.208 0.192 ;
    END
  END o0[39]
  PIN o0[3]
    DIRECTION OUTPUT ;
    USE SIGNAL ;
    PORT
      LAYER M5 ;
        RECT  5.04 0 5.064 0.192 ;
    END
  END o0[3]
  PIN o0[40]
    DIRECTION OUTPUT ;
    USE SIGNAL ;
    PORT
      LAYER M5 ;
        RECT  11.376 0 11.4 0.192 ;
    END
  END o0[40]
  PIN o0[41]
    DIRECTION OUTPUT ;
    USE SIGNAL ;
    PORT
      LAYER M5 ;
        RECT  11.568 0 11.592 0.192 ;
    END
  END o0[41]
  PIN o0[42]
    DIRECTION OUTPUT ;
    USE SIGNAL ;
    PORT
      LAYER M5 ;
        RECT  11.712 0 11.736 0.192 ;
    END
  END o0[42]
  PIN o0[43]
    DIRECTION OUTPUT ;
    USE SIGNAL ;
    PORT
      LAYER M5 ;
        RECT  11.904 0 11.928 0.192 ;
    END
  END o0[43]
  PIN o0[44]
    DIRECTION OUTPUT ;
    USE SIGNAL ;
    PORT
      LAYER M5 ;
        RECT  12.048 0 12.072 0.192 ;
    END
  END o0[44]
  PIN o0[45]
    DIRECTION OUTPUT ;
    USE SIGNAL ;
    PORT
      LAYER M5 ;
        RECT  12.24 0 12.264 0.192 ;
    END
  END o0[45]
  PIN o0[46]
    DIRECTION OUTPUT ;
    USE SIGNAL ;
    PORT
      LAYER M5 ;
        RECT  12.432 0 12.456 0.192 ;
    END
  END o0[46]
  PIN o0[47]
    DIRECTION OUTPUT ;
    USE SIGNAL ;
    PORT
      LAYER M5 ;
        RECT  12.576 0 12.6 0.192 ;
    END
  END o0[47]
  PIN o0[48]
    DIRECTION OUTPUT ;
    USE SIGNAL ;
    PORT
      LAYER M5 ;
        RECT  12.768 0 12.792 0.192 ;
    END
  END o0[48]
  PIN o0[49]
    DIRECTION OUTPUT ;
    USE SIGNAL ;
    PORT
      LAYER M5 ;
        RECT  12.912 0 12.936 0.192 ;
    END
  END o0[49]
  PIN o0[4]
    DIRECTION OUTPUT ;
    USE SIGNAL ;
    PORT
      LAYER M5 ;
        RECT  5.184 0 5.208 0.192 ;
    END
  END o0[4]
  PIN o0[50]
    DIRECTION OUTPUT ;
    USE SIGNAL ;
    PORT
      LAYER M5 ;
        RECT  13.104 0 13.128 0.192 ;
    END
  END o0[50]
  PIN o0[51]
    DIRECTION OUTPUT ;
    USE SIGNAL ;
    PORT
      LAYER M5 ;
        RECT  13.248 0 13.272 0.192 ;
    END
  END o0[51]
  PIN o0[52]
    DIRECTION OUTPUT ;
    USE SIGNAL ;
    PORT
      LAYER M5 ;
        RECT  13.44 0 13.464 0.192 ;
    END
  END o0[52]
  PIN o0[53]
    DIRECTION OUTPUT ;
    USE SIGNAL ;
    PORT
      LAYER M5 ;
        RECT  13.632 0 13.656 0.192 ;
    END
  END o0[53]
  PIN o0[54]
    DIRECTION OUTPUT ;
    USE SIGNAL ;
    PORT
      LAYER M5 ;
        RECT  13.776 0 13.8 0.192 ;
    END
  END o0[54]
  PIN o0[55]
    DIRECTION OUTPUT ;
    USE SIGNAL ;
    PORT
      LAYER M5 ;
        RECT  13.968 0 13.992 0.192 ;
    END
  END o0[55]
  PIN o0[56]
    DIRECTION OUTPUT ;
    USE SIGNAL ;
    PORT
      LAYER M5 ;
        RECT  14.112 0 14.136 0.192 ;
    END
  END o0[56]
  PIN o0[57]
    DIRECTION OUTPUT ;
    USE SIGNAL ;
    PORT
      LAYER M5 ;
        RECT  14.304 0 14.328 0.192 ;
    END
  END o0[57]
  PIN o0[58]
    DIRECTION OUTPUT ;
    USE SIGNAL ;
    PORT
      LAYER M5 ;
        RECT  14.448 0 14.472 0.192 ;
    END
  END o0[58]
  PIN o0[59]
    DIRECTION OUTPUT ;
    USE SIGNAL ;
    PORT
      LAYER M5 ;
        RECT  14.64 0 14.664 0.192 ;
    END
  END o0[59]
  PIN o0[5]
    DIRECTION OUTPUT ;
    USE SIGNAL ;
    PORT
      LAYER M5 ;
        RECT  5.376 0 5.4 0.192 ;
    END
  END o0[5]
  PIN o0[60]
    DIRECTION OUTPUT ;
    USE SIGNAL ;
    PORT
      LAYER M5 ;
        RECT  14.832 0 14.856 0.192 ;
    END
  END o0[60]
  PIN o0[61]
    DIRECTION OUTPUT ;
    USE SIGNAL ;
    PORT
      LAYER M5 ;
        RECT  14.976 0 15 0.192 ;
    END
  END o0[61]
  PIN o0[62]
    DIRECTION OUTPUT ;
    USE SIGNAL ;
    PORT
      LAYER M5 ;
        RECT  15.168 0 15.192 0.192 ;
    END
  END o0[62]
  PIN o0[63]
    DIRECTION OUTPUT ;
    USE SIGNAL ;
    PORT
      LAYER M5 ;
        RECT  15.312 0 15.336 0.192 ;
    END
  END o0[63]
  PIN o0[64]
    DIRECTION OUTPUT ;
    USE SIGNAL ;
    PORT
      LAYER M5 ;
        RECT  15.504 0 15.528 0.192 ;
    END
  END o0[64]
  PIN o0[65]
    DIRECTION OUTPUT ;
    USE SIGNAL ;
    PORT
      LAYER M5 ;
        RECT  15.696 0 15.72 0.192 ;
    END
  END o0[65]
  PIN o0[66]
    DIRECTION OUTPUT ;
    USE SIGNAL ;
    PORT
      LAYER M5 ;
        RECT  15.84 0 15.864 0.192 ;
    END
  END o0[66]
  PIN o0[67]
    DIRECTION OUTPUT ;
    USE SIGNAL ;
    PORT
      LAYER M5 ;
        RECT  16.032 0 16.056 0.192 ;
    END
  END o0[67]
  PIN o0[68]
    DIRECTION OUTPUT ;
    USE SIGNAL ;
    PORT
      LAYER M5 ;
        RECT  16.368 0 16.392 0.192 ;
    END
  END o0[68]
  PIN o0[69]
    DIRECTION OUTPUT ;
    USE SIGNAL ;
    PORT
      LAYER M5 ;
        RECT  16.512 0 16.536 0.192 ;
    END
  END o0[69]
  PIN o0[6]
    DIRECTION OUTPUT ;
    USE SIGNAL ;
    PORT
      LAYER M5 ;
        RECT  5.52 0 5.544 0.192 ;
    END
  END o0[6]
  PIN o0[70]
    DIRECTION OUTPUT ;
    USE SIGNAL ;
    PORT
      LAYER M5 ;
        RECT  16.704 0 16.728 0.192 ;
    END
  END o0[70]
  PIN o0[71]
    DIRECTION OUTPUT ;
    USE SIGNAL ;
    PORT
      LAYER M5 ;
        RECT  16.896 0 16.92 0.192 ;
    END
  END o0[71]
  PIN o0[72]
    DIRECTION OUTPUT ;
    USE SIGNAL ;
    PORT
      LAYER M5 ;
        RECT  17.04 0 17.064 0.192 ;
    END
  END o0[72]
  PIN o0[73]
    DIRECTION OUTPUT ;
    USE SIGNAL ;
    PORT
      LAYER M5 ;
        RECT  17.232 0 17.256 0.192 ;
    END
  END o0[73]
  PIN o0[74]
    DIRECTION OUTPUT ;
    USE SIGNAL ;
    PORT
      LAYER M5 ;
        RECT  17.376 0 17.4 0.192 ;
    END
  END o0[74]
  PIN o0[75]
    DIRECTION OUTPUT ;
    USE SIGNAL ;
    PORT
      LAYER M5 ;
        RECT  17.568 0 17.592 0.192 ;
    END
  END o0[75]
  PIN o0[76]
    DIRECTION OUTPUT ;
    USE SIGNAL ;
    PORT
      LAYER M5 ;
        RECT  17.712 0 17.736 0.192 ;
    END
  END o0[76]
  PIN o0[77]
    DIRECTION OUTPUT ;
    USE SIGNAL ;
    PORT
      LAYER M5 ;
        RECT  17.904 0 17.928 0.192 ;
    END
  END o0[77]
  PIN o0[78]
    DIRECTION OUTPUT ;
    USE SIGNAL ;
    PORT
      LAYER M5 ;
        RECT  18.096 0 18.12 0.192 ;
    END
  END o0[78]
  PIN o0[79]
    DIRECTION OUTPUT ;
    USE SIGNAL ;
    PORT
      LAYER M5 ;
        RECT  18.24 0 18.264 0.192 ;
    END
  END o0[79]
  PIN o0[7]
    DIRECTION OUTPUT ;
    USE SIGNAL ;
    PORT
      LAYER M5 ;
        RECT  5.712 0 5.736 0.192 ;
    END
  END o0[7]
  PIN o0[80]
    DIRECTION OUTPUT ;
    USE SIGNAL ;
    PORT
      LAYER M5 ;
        RECT  18.432 0 18.456 0.192 ;
    END
  END o0[80]
  PIN o0[81]
    DIRECTION OUTPUT ;
    USE SIGNAL ;
    PORT
      LAYER M5 ;
        RECT  18.576 0 18.6 0.192 ;
    END
  END o0[81]
  PIN o0[82]
    DIRECTION OUTPUT ;
    USE SIGNAL ;
    PORT
      LAYER M5 ;
        RECT  18.768 0 18.792 0.192 ;
    END
  END o0[82]
  PIN o0[83]
    DIRECTION OUTPUT ;
    USE SIGNAL ;
    PORT
      LAYER M5 ;
        RECT  18.96 0 18.984 0.192 ;
    END
  END o0[83]
  PIN o0[84]
    DIRECTION OUTPUT ;
    USE SIGNAL ;
    PORT
      LAYER M5 ;
        RECT  19.104 0 19.128 0.192 ;
    END
  END o0[84]
  PIN o0[85]
    DIRECTION OUTPUT ;
    USE SIGNAL ;
    PORT
      LAYER M5 ;
        RECT  19.296 0 19.32 0.192 ;
    END
  END o0[85]
  PIN o0[86]
    DIRECTION OUTPUT ;
    USE SIGNAL ;
    PORT
      LAYER M5 ;
        RECT  19.44 0 19.464 0.192 ;
    END
  END o0[86]
  PIN o0[87]
    DIRECTION OUTPUT ;
    USE SIGNAL ;
    PORT
      LAYER M5 ;
        RECT  19.632 0 19.656 0.192 ;
    END
  END o0[87]
  PIN o0[88]
    DIRECTION OUTPUT ;
    USE SIGNAL ;
    PORT
      LAYER M5 ;
        RECT  19.776 0 19.8 0.192 ;
    END
  END o0[88]
  PIN o0[89]
    DIRECTION OUTPUT ;
    USE SIGNAL ;
    PORT
      LAYER M5 ;
        RECT  19.968 0 19.992 0.192 ;
    END
  END o0[89]
  PIN o0[8]
    DIRECTION OUTPUT ;
    USE SIGNAL ;
    PORT
      LAYER M5 ;
        RECT  5.904 0 5.928 0.192 ;
    END
  END o0[8]
  PIN o0[90]
    DIRECTION OUTPUT ;
    USE SIGNAL ;
    PORT
      LAYER M5 ;
        RECT  20.16 0 20.184 0.192 ;
    END
  END o0[90]
  PIN o0[91]
    DIRECTION OUTPUT ;
    USE SIGNAL ;
    PORT
      LAYER M5 ;
        RECT  20.304 0 20.328 0.192 ;
    END
  END o0[91]
  PIN o0[92]
    DIRECTION OUTPUT ;
    USE SIGNAL ;
    PORT
      LAYER M5 ;
        RECT  20.496 0 20.52 0.192 ;
    END
  END o0[92]
  PIN o0[93]
    DIRECTION OUTPUT ;
    USE SIGNAL ;
    PORT
      LAYER M5 ;
        RECT  20.64 0 20.664 0.192 ;
    END
  END o0[93]
  PIN o0[94]
    DIRECTION OUTPUT ;
    USE SIGNAL ;
    PORT
      LAYER M5 ;
        RECT  20.832 0 20.856 0.192 ;
    END
  END o0[94]
  PIN o0[95]
    DIRECTION OUTPUT ;
    USE SIGNAL ;
    PORT
      LAYER M5 ;
        RECT  20.976 0 21 0.192 ;
    END
  END o0[95]
  PIN o0[96]
    DIRECTION OUTPUT ;
    USE SIGNAL ;
    PORT
      LAYER M5 ;
        RECT  21.168 0 21.192 0.192 ;
    END
  END o0[96]
  PIN o0[97]
    DIRECTION OUTPUT ;
    USE SIGNAL ;
    PORT
      LAYER M5 ;
        RECT  21.36 0 21.384 0.192 ;
    END
  END o0[97]
  PIN o0[98]
    DIRECTION OUTPUT ;
    USE SIGNAL ;
    PORT
      LAYER M5 ;
        RECT  21.504 0 21.528 0.192 ;
    END
  END o0[98]
  PIN o0[99]
    DIRECTION OUTPUT ;
    USE SIGNAL ;
    PORT
      LAYER M5 ;
        RECT  21.696 0 21.72 0.192 ;
    END
  END o0[99]
  PIN o0[9]
    DIRECTION OUTPUT ;
    USE SIGNAL ;
    PORT
      LAYER M5 ;
        RECT  6.048 0 6.072 0.192 ;
    END
  END o0[9]
  PIN o1[0]
    DIRECTION OUTPUT ;
    USE SIGNAL ;
    PORT
      LAYER M5 ;
        RECT  28.272 0 28.296 0.192 ;
    END
  END o1[0]
  PIN o1[100]
    DIRECTION OUTPUT ;
    USE SIGNAL ;
    PORT
      LAYER M5 ;
        RECT  45.6 0 45.624 0.192 ;
    END
  END o1[100]
  PIN o1[101]
    DIRECTION OUTPUT ;
    USE SIGNAL ;
    PORT
      LAYER M5 ;
        RECT  45.792 0 45.816 0.192 ;
    END
  END o1[101]
  PIN o1[102]
    DIRECTION OUTPUT ;
    USE SIGNAL ;
    PORT
      LAYER M5 ;
        RECT  45.936 0 45.96 0.192 ;
    END
  END o1[102]
  PIN o1[103]
    DIRECTION OUTPUT ;
    USE SIGNAL ;
    PORT
      LAYER M5 ;
        RECT  46.128 0 46.152 0.192 ;
    END
  END o1[103]
  PIN o1[104]
    DIRECTION OUTPUT ;
    USE SIGNAL ;
    PORT
      LAYER M5 ;
        RECT  46.32 0 46.344 0.192 ;
    END
  END o1[104]
  PIN o1[105]
    DIRECTION OUTPUT ;
    USE SIGNAL ;
    PORT
      LAYER M5 ;
        RECT  46.464 0 46.488 0.192 ;
    END
  END o1[105]
  PIN o1[106]
    DIRECTION OUTPUT ;
    USE SIGNAL ;
    PORT
      LAYER M5 ;
        RECT  46.656 0 46.68 0.192 ;
    END
  END o1[106]
  PIN o1[107]
    DIRECTION OUTPUT ;
    USE SIGNAL ;
    PORT
      LAYER M5 ;
        RECT  46.8 0 46.824 0.192 ;
    END
  END o1[107]
  PIN o1[108]
    DIRECTION OUTPUT ;
    USE SIGNAL ;
    PORT
      LAYER M5 ;
        RECT  46.992 0 47.016 0.192 ;
    END
  END o1[108]
  PIN o1[109]
    DIRECTION OUTPUT ;
    USE SIGNAL ;
    PORT
      LAYER M5 ;
        RECT  47.184 0 47.208 0.192 ;
    END
  END o1[109]
  PIN o1[10]
    DIRECTION OUTPUT ;
    USE SIGNAL ;
    PORT
      LAYER M5 ;
        RECT  30 0 30.024 0.192 ;
    END
  END o1[10]
  PIN o1[110]
    DIRECTION OUTPUT ;
    USE SIGNAL ;
    PORT
      LAYER M5 ;
        RECT  47.328 0 47.352 0.192 ;
    END
  END o1[110]
  PIN o1[111]
    DIRECTION OUTPUT ;
    USE SIGNAL ;
    PORT
      LAYER M5 ;
        RECT  47.52 0 47.544 0.192 ;
    END
  END o1[111]
  PIN o1[112]
    DIRECTION OUTPUT ;
    USE SIGNAL ;
    PORT
      LAYER M5 ;
        RECT  47.664 0 47.688 0.192 ;
    END
  END o1[112]
  PIN o1[113]
    DIRECTION OUTPUT ;
    USE SIGNAL ;
    PORT
      LAYER M5 ;
        RECT  47.856 0 47.88 0.192 ;
    END
  END o1[113]
  PIN o1[114]
    DIRECTION OUTPUT ;
    USE SIGNAL ;
    PORT
      LAYER M5 ;
        RECT  48 0 48.024 0.192 ;
    END
  END o1[114]
  PIN o1[115]
    DIRECTION OUTPUT ;
    USE SIGNAL ;
    PORT
      LAYER M5 ;
        RECT  48.192 0 48.216 0.192 ;
    END
  END o1[115]
  PIN o1[116]
    DIRECTION OUTPUT ;
    USE SIGNAL ;
    PORT
      LAYER M5 ;
        RECT  48.384 0 48.408 0.192 ;
    END
  END o1[116]
  PIN o1[117]
    DIRECTION OUTPUT ;
    USE SIGNAL ;
    PORT
      LAYER M5 ;
        RECT  48.528 0 48.552 0.192 ;
    END
  END o1[117]
  PIN o1[118]
    DIRECTION OUTPUT ;
    USE SIGNAL ;
    PORT
      LAYER M5 ;
        RECT  48.72 0 48.744 0.192 ;
    END
  END o1[118]
  PIN o1[119]
    DIRECTION OUTPUT ;
    USE SIGNAL ;
    PORT
      LAYER M5 ;
        RECT  48.864 0 48.888 0.192 ;
    END
  END o1[119]
  PIN o1[11]
    DIRECTION OUTPUT ;
    USE SIGNAL ;
    PORT
      LAYER M5 ;
        RECT  30.144 0 30.168 0.192 ;
    END
  END o1[11]
  PIN o1[120]
    DIRECTION OUTPUT ;
    USE SIGNAL ;
    PORT
      LAYER M5 ;
        RECT  49.056 0 49.08 0.192 ;
    END
  END o1[120]
  PIN o1[121]
    DIRECTION OUTPUT ;
    USE SIGNAL ;
    PORT
      LAYER M5 ;
        RECT  49.2 0 49.224 0.192 ;
    END
  END o1[121]
  PIN o1[122]
    DIRECTION OUTPUT ;
    USE SIGNAL ;
    PORT
      LAYER M5 ;
        RECT  49.392 0 49.416 0.192 ;
    END
  END o1[122]
  PIN o1[123]
    DIRECTION OUTPUT ;
    USE SIGNAL ;
    PORT
      LAYER M5 ;
        RECT  49.584 0 49.608 0.192 ;
    END
  END o1[123]
  PIN o1[124]
    DIRECTION OUTPUT ;
    USE SIGNAL ;
    PORT
      LAYER M5 ;
        RECT  49.728 0 49.752 0.192 ;
    END
  END o1[124]
  PIN o1[125]
    DIRECTION OUTPUT ;
    USE SIGNAL ;
    PORT
      LAYER M5 ;
        RECT  49.92 0 49.944 0.192 ;
    END
  END o1[125]
  PIN o1[126]
    DIRECTION OUTPUT ;
    USE SIGNAL ;
    PORT
      LAYER M5 ;
        RECT  50.064 0 50.088 0.192 ;
    END
  END o1[126]
  PIN o1[127]
    DIRECTION OUTPUT ;
    USE SIGNAL ;
    PORT
      LAYER M5 ;
        RECT  50.256 0 50.28 0.192 ;
    END
  END o1[127]
  PIN o1[128]
    DIRECTION OUTPUT ;
    USE SIGNAL ;
    PORT
      LAYER M5 ;
        RECT  50.448 0 50.472 0.192 ;
    END
  END o1[128]
  PIN o1[129]
    DIRECTION OUTPUT ;
    USE SIGNAL ;
    PORT
      LAYER M5 ;
        RECT  50.592 0 50.616 0.192 ;
    END
  END o1[129]
  PIN o1[12]
    DIRECTION OUTPUT ;
    USE SIGNAL ;
    PORT
      LAYER M5 ;
        RECT  30.336 0 30.36 0.192 ;
    END
  END o1[12]
  PIN o1[130]
    DIRECTION OUTPUT ;
    USE SIGNAL ;
    PORT
      LAYER M5 ;
        RECT  50.784 0 50.808 0.192 ;
    END
  END o1[130]
  PIN o1[131]
    DIRECTION OUTPUT ;
    USE SIGNAL ;
    PORT
      LAYER M5 ;
        RECT  50.928 0 50.952 0.192 ;
    END
  END o1[131]
  PIN o1[132]
    DIRECTION OUTPUT ;
    USE SIGNAL ;
    PORT
      LAYER M5 ;
        RECT  51.12 0 51.144 0.192 ;
    END
  END o1[132]
  PIN o1[133]
    DIRECTION OUTPUT ;
    USE SIGNAL ;
    PORT
      LAYER M5 ;
        RECT  51.264 0 51.288 0.192 ;
    END
  END o1[133]
  PIN o1[134]
    DIRECTION OUTPUT ;
    USE SIGNAL ;
    PORT
      LAYER M5 ;
        RECT  51.456 0 51.48 0.192 ;
    END
  END o1[134]
  PIN o1[135]
    DIRECTION OUTPUT ;
    USE SIGNAL ;
    PORT
      LAYER M5 ;
        RECT  51.648 0 51.672 0.192 ;
    END
  END o1[135]
  PIN o1[13]
    DIRECTION OUTPUT ;
    USE SIGNAL ;
    PORT
      LAYER M5 ;
        RECT  30.48 0 30.504 0.192 ;
    END
  END o1[13]
  PIN o1[14]
    DIRECTION OUTPUT ;
    USE SIGNAL ;
    PORT
      LAYER M5 ;
        RECT  30.672 0 30.696 0.192 ;
    END
  END o1[14]
  PIN o1[15]
    DIRECTION OUTPUT ;
    USE SIGNAL ;
    PORT
      LAYER M5 ;
        RECT  30.864 0 30.888 0.192 ;
    END
  END o1[15]
  PIN o1[16]
    DIRECTION OUTPUT ;
    USE SIGNAL ;
    PORT
      LAYER M5 ;
        RECT  31.008 0 31.032 0.192 ;
    END
  END o1[16]
  PIN o1[17]
    DIRECTION OUTPUT ;
    USE SIGNAL ;
    PORT
      LAYER M5 ;
        RECT  31.2 0 31.224 0.192 ;
    END
  END o1[17]
  PIN o1[18]
    DIRECTION OUTPUT ;
    USE SIGNAL ;
    PORT
      LAYER M5 ;
        RECT  31.344 0 31.368 0.192 ;
    END
  END o1[18]
  PIN o1[19]
    DIRECTION OUTPUT ;
    USE SIGNAL ;
    PORT
      LAYER M5 ;
        RECT  31.536 0 31.56 0.192 ;
    END
  END o1[19]
  PIN o1[1]
    DIRECTION OUTPUT ;
    USE SIGNAL ;
    PORT
      LAYER M5 ;
        RECT  28.416 0 28.44 0.192 ;
    END
  END o1[1]
  PIN o1[20]
    DIRECTION OUTPUT ;
    USE SIGNAL ;
    PORT
      LAYER M5 ;
        RECT  31.68 0 31.704 0.192 ;
    END
  END o1[20]
  PIN o1[21]
    DIRECTION OUTPUT ;
    USE SIGNAL ;
    PORT
      LAYER M5 ;
        RECT  31.872 0 31.896 0.192 ;
    END
  END o1[21]
  PIN o1[22]
    DIRECTION OUTPUT ;
    USE SIGNAL ;
    PORT
      LAYER M5 ;
        RECT  32.064 0 32.088 0.192 ;
    END
  END o1[22]
  PIN o1[23]
    DIRECTION OUTPUT ;
    USE SIGNAL ;
    PORT
      LAYER M5 ;
        RECT  32.208 0 32.232 0.192 ;
    END
  END o1[23]
  PIN o1[24]
    DIRECTION OUTPUT ;
    USE SIGNAL ;
    PORT
      LAYER M5 ;
        RECT  32.4 0 32.424 0.192 ;
    END
  END o1[24]
  PIN o1[25]
    DIRECTION OUTPUT ;
    USE SIGNAL ;
    PORT
      LAYER M5 ;
        RECT  32.544 0 32.568 0.192 ;
    END
  END o1[25]
  PIN o1[26]
    DIRECTION OUTPUT ;
    USE SIGNAL ;
    PORT
      LAYER M5 ;
        RECT  32.736 0 32.76 0.192 ;
    END
  END o1[26]
  PIN o1[27]
    DIRECTION OUTPUT ;
    USE SIGNAL ;
    PORT
      LAYER M5 ;
        RECT  32.928 0 32.952 0.192 ;
    END
  END o1[27]
  PIN o1[28]
    DIRECTION OUTPUT ;
    USE SIGNAL ;
    PORT
      LAYER M5 ;
        RECT  33.072 0 33.096 0.192 ;
    END
  END o1[28]
  PIN o1[29]
    DIRECTION OUTPUT ;
    USE SIGNAL ;
    PORT
      LAYER M5 ;
        RECT  33.264 0 33.288 0.192 ;
    END
  END o1[29]
  PIN o1[2]
    DIRECTION OUTPUT ;
    USE SIGNAL ;
    PORT
      LAYER M5 ;
        RECT  28.608 0 28.632 0.192 ;
    END
  END o1[2]
  PIN o1[30]
    DIRECTION OUTPUT ;
    USE SIGNAL ;
    PORT
      LAYER M5 ;
        RECT  33.408 0 33.432 0.192 ;
    END
  END o1[30]
  PIN o1[31]
    DIRECTION OUTPUT ;
    USE SIGNAL ;
    PORT
      LAYER M5 ;
        RECT  33.6 0 33.624 0.192 ;
    END
  END o1[31]
  PIN o1[32]
    DIRECTION OUTPUT ;
    USE SIGNAL ;
    PORT
      LAYER M5 ;
        RECT  33.744 0 33.768 0.192 ;
    END
  END o1[32]
  PIN o1[33]
    DIRECTION OUTPUT ;
    USE SIGNAL ;
    PORT
      LAYER M5 ;
        RECT  33.936 0 33.96 0.192 ;
    END
  END o1[33]
  PIN o1[34]
    DIRECTION OUTPUT ;
    USE SIGNAL ;
    PORT
      LAYER M5 ;
        RECT  34.128 0 34.152 0.192 ;
    END
  END o1[34]
  PIN o1[35]
    DIRECTION OUTPUT ;
    USE SIGNAL ;
    PORT
      LAYER M5 ;
        RECT  34.272 0 34.296 0.192 ;
    END
  END o1[35]
  PIN o1[36]
    DIRECTION OUTPUT ;
    USE SIGNAL ;
    PORT
      LAYER M5 ;
        RECT  34.464 0 34.488 0.192 ;
    END
  END o1[36]
  PIN o1[37]
    DIRECTION OUTPUT ;
    USE SIGNAL ;
    PORT
      LAYER M5 ;
        RECT  34.608 0 34.632 0.192 ;
    END
  END o1[37]
  PIN o1[38]
    DIRECTION OUTPUT ;
    USE SIGNAL ;
    PORT
      LAYER M5 ;
        RECT  34.8 0 34.824 0.192 ;
    END
  END o1[38]
  PIN o1[39]
    DIRECTION OUTPUT ;
    USE SIGNAL ;
    PORT
      LAYER M5 ;
        RECT  34.944 0 34.968 0.192 ;
    END
  END o1[39]
  PIN o1[3]
    DIRECTION OUTPUT ;
    USE SIGNAL ;
    PORT
      LAYER M5 ;
        RECT  28.8 0 28.824 0.192 ;
    END
  END o1[3]
  PIN o1[40]
    DIRECTION OUTPUT ;
    USE SIGNAL ;
    PORT
      LAYER M5 ;
        RECT  35.136 0 35.16 0.192 ;
    END
  END o1[40]
  PIN o1[41]
    DIRECTION OUTPUT ;
    USE SIGNAL ;
    PORT
      LAYER M5 ;
        RECT  35.328 0 35.352 0.192 ;
    END
  END o1[41]
  PIN o1[42]
    DIRECTION OUTPUT ;
    USE SIGNAL ;
    PORT
      LAYER M5 ;
        RECT  35.472 0 35.496 0.192 ;
    END
  END o1[42]
  PIN o1[43]
    DIRECTION OUTPUT ;
    USE SIGNAL ;
    PORT
      LAYER M5 ;
        RECT  35.664 0 35.688 0.192 ;
    END
  END o1[43]
  PIN o1[44]
    DIRECTION OUTPUT ;
    USE SIGNAL ;
    PORT
      LAYER M5 ;
        RECT  35.808 0 35.832 0.192 ;
    END
  END o1[44]
  PIN o1[45]
    DIRECTION OUTPUT ;
    USE SIGNAL ;
    PORT
      LAYER M5 ;
        RECT  36 0 36.024 0.192 ;
    END
  END o1[45]
  PIN o1[46]
    DIRECTION OUTPUT ;
    USE SIGNAL ;
    PORT
      LAYER M5 ;
        RECT  36.192 0 36.216 0.192 ;
    END
  END o1[46]
  PIN o1[47]
    DIRECTION OUTPUT ;
    USE SIGNAL ;
    PORT
      LAYER M5 ;
        RECT  36.336 0 36.36 0.192 ;
    END
  END o1[47]
  PIN o1[48]
    DIRECTION OUTPUT ;
    USE SIGNAL ;
    PORT
      LAYER M5 ;
        RECT  36.528 0 36.552 0.192 ;
    END
  END o1[48]
  PIN o1[49]
    DIRECTION OUTPUT ;
    USE SIGNAL ;
    PORT
      LAYER M5 ;
        RECT  36.672 0 36.696 0.192 ;
    END
  END o1[49]
  PIN o1[4]
    DIRECTION OUTPUT ;
    USE SIGNAL ;
    PORT
      LAYER M5 ;
        RECT  28.944 0 28.968 0.192 ;
    END
  END o1[4]
  PIN o1[50]
    DIRECTION OUTPUT ;
    USE SIGNAL ;
    PORT
      LAYER M5 ;
        RECT  36.864 0 36.888 0.192 ;
    END
  END o1[50]
  PIN o1[51]
    DIRECTION OUTPUT ;
    USE SIGNAL ;
    PORT
      LAYER M5 ;
        RECT  37.008 0 37.032 0.192 ;
    END
  END o1[51]
  PIN o1[52]
    DIRECTION OUTPUT ;
    USE SIGNAL ;
    PORT
      LAYER M5 ;
        RECT  37.2 0 37.224 0.192 ;
    END
  END o1[52]
  PIN o1[53]
    DIRECTION OUTPUT ;
    USE SIGNAL ;
    PORT
      LAYER M5 ;
        RECT  37.392 0 37.416 0.192 ;
    END
  END o1[53]
  PIN o1[54]
    DIRECTION OUTPUT ;
    USE SIGNAL ;
    PORT
      LAYER M5 ;
        RECT  37.536 0 37.56 0.192 ;
    END
  END o1[54]
  PIN o1[55]
    DIRECTION OUTPUT ;
    USE SIGNAL ;
    PORT
      LAYER M5 ;
        RECT  37.728 0 37.752 0.192 ;
    END
  END o1[55]
  PIN o1[56]
    DIRECTION OUTPUT ;
    USE SIGNAL ;
    PORT
      LAYER M5 ;
        RECT  37.872 0 37.896 0.192 ;
    END
  END o1[56]
  PIN o1[57]
    DIRECTION OUTPUT ;
    USE SIGNAL ;
    PORT
      LAYER M5 ;
        RECT  38.064 0 38.088 0.192 ;
    END
  END o1[57]
  PIN o1[58]
    DIRECTION OUTPUT ;
    USE SIGNAL ;
    PORT
      LAYER M5 ;
        RECT  38.208 0 38.232 0.192 ;
    END
  END o1[58]
  PIN o1[59]
    DIRECTION OUTPUT ;
    USE SIGNAL ;
    PORT
      LAYER M5 ;
        RECT  38.4 0 38.424 0.192 ;
    END
  END o1[59]
  PIN o1[5]
    DIRECTION OUTPUT ;
    USE SIGNAL ;
    PORT
      LAYER M5 ;
        RECT  29.136 0 29.16 0.192 ;
    END
  END o1[5]
  PIN o1[60]
    DIRECTION OUTPUT ;
    USE SIGNAL ;
    PORT
      LAYER M5 ;
        RECT  38.592 0 38.616 0.192 ;
    END
  END o1[60]
  PIN o1[61]
    DIRECTION OUTPUT ;
    USE SIGNAL ;
    PORT
      LAYER M5 ;
        RECT  38.736 0 38.76 0.192 ;
    END
  END o1[61]
  PIN o1[62]
    DIRECTION OUTPUT ;
    USE SIGNAL ;
    PORT
      LAYER M5 ;
        RECT  38.928 0 38.952 0.192 ;
    END
  END o1[62]
  PIN o1[63]
    DIRECTION OUTPUT ;
    USE SIGNAL ;
    PORT
      LAYER M5 ;
        RECT  39.072 0 39.096 0.192 ;
    END
  END o1[63]
  PIN o1[64]
    DIRECTION OUTPUT ;
    USE SIGNAL ;
    PORT
      LAYER M5 ;
        RECT  39.264 0 39.288 0.192 ;
    END
  END o1[64]
  PIN o1[65]
    DIRECTION OUTPUT ;
    USE SIGNAL ;
    PORT
      LAYER M5 ;
        RECT  39.456 0 39.48 0.192 ;
    END
  END o1[65]
  PIN o1[66]
    DIRECTION OUTPUT ;
    USE SIGNAL ;
    PORT
      LAYER M5 ;
        RECT  39.6 0 39.624 0.192 ;
    END
  END o1[66]
  PIN o1[67]
    DIRECTION OUTPUT ;
    USE SIGNAL ;
    PORT
      LAYER M5 ;
        RECT  39.792 0 39.816 0.192 ;
    END
  END o1[67]
  PIN o1[68]
    DIRECTION OUTPUT ;
    USE SIGNAL ;
    PORT
      LAYER M5 ;
        RECT  40.128 0 40.152 0.192 ;
    END
  END o1[68]
  PIN o1[69]
    DIRECTION OUTPUT ;
    USE SIGNAL ;
    PORT
      LAYER M5 ;
        RECT  40.272 0 40.296 0.192 ;
    END
  END o1[69]
  PIN o1[6]
    DIRECTION OUTPUT ;
    USE SIGNAL ;
    PORT
      LAYER M5 ;
        RECT  29.28 0 29.304 0.192 ;
    END
  END o1[6]
  PIN o1[70]
    DIRECTION OUTPUT ;
    USE SIGNAL ;
    PORT
      LAYER M5 ;
        RECT  40.464 0 40.488 0.192 ;
    END
  END o1[70]
  PIN o1[71]
    DIRECTION OUTPUT ;
    USE SIGNAL ;
    PORT
      LAYER M5 ;
        RECT  40.656 0 40.68 0.192 ;
    END
  END o1[71]
  PIN o1[72]
    DIRECTION OUTPUT ;
    USE SIGNAL ;
    PORT
      LAYER M5 ;
        RECT  40.8 0 40.824 0.192 ;
    END
  END o1[72]
  PIN o1[73]
    DIRECTION OUTPUT ;
    USE SIGNAL ;
    PORT
      LAYER M5 ;
        RECT  40.992 0 41.016 0.192 ;
    END
  END o1[73]
  PIN o1[74]
    DIRECTION OUTPUT ;
    USE SIGNAL ;
    PORT
      LAYER M5 ;
        RECT  41.136 0 41.16 0.192 ;
    END
  END o1[74]
  PIN o1[75]
    DIRECTION OUTPUT ;
    USE SIGNAL ;
    PORT
      LAYER M5 ;
        RECT  41.328 0 41.352 0.192 ;
    END
  END o1[75]
  PIN o1[76]
    DIRECTION OUTPUT ;
    USE SIGNAL ;
    PORT
      LAYER M5 ;
        RECT  41.472 0 41.496 0.192 ;
    END
  END o1[76]
  PIN o1[77]
    DIRECTION OUTPUT ;
    USE SIGNAL ;
    PORT
      LAYER M5 ;
        RECT  41.664 0 41.688 0.192 ;
    END
  END o1[77]
  PIN o1[78]
    DIRECTION OUTPUT ;
    USE SIGNAL ;
    PORT
      LAYER M5 ;
        RECT  41.856 0 41.88 0.192 ;
    END
  END o1[78]
  PIN o1[79]
    DIRECTION OUTPUT ;
    USE SIGNAL ;
    PORT
      LAYER M5 ;
        RECT  42 0 42.024 0.192 ;
    END
  END o1[79]
  PIN o1[7]
    DIRECTION OUTPUT ;
    USE SIGNAL ;
    PORT
      LAYER M5 ;
        RECT  29.472 0 29.496 0.192 ;
    END
  END o1[7]
  PIN o1[80]
    DIRECTION OUTPUT ;
    USE SIGNAL ;
    PORT
      LAYER M5 ;
        RECT  42.192 0 42.216 0.192 ;
    END
  END o1[80]
  PIN o1[81]
    DIRECTION OUTPUT ;
    USE SIGNAL ;
    PORT
      LAYER M5 ;
        RECT  42.336 0 42.36 0.192 ;
    END
  END o1[81]
  PIN o1[82]
    DIRECTION OUTPUT ;
    USE SIGNAL ;
    PORT
      LAYER M5 ;
        RECT  42.528 0 42.552 0.192 ;
    END
  END o1[82]
  PIN o1[83]
    DIRECTION OUTPUT ;
    USE SIGNAL ;
    PORT
      LAYER M5 ;
        RECT  42.72 0 42.744 0.192 ;
    END
  END o1[83]
  PIN o1[84]
    DIRECTION OUTPUT ;
    USE SIGNAL ;
    PORT
      LAYER M5 ;
        RECT  42.864 0 42.888 0.192 ;
    END
  END o1[84]
  PIN o1[85]
    DIRECTION OUTPUT ;
    USE SIGNAL ;
    PORT
      LAYER M5 ;
        RECT  43.056 0 43.08 0.192 ;
    END
  END o1[85]
  PIN o1[86]
    DIRECTION OUTPUT ;
    USE SIGNAL ;
    PORT
      LAYER M5 ;
        RECT  43.2 0 43.224 0.192 ;
    END
  END o1[86]
  PIN o1[87]
    DIRECTION OUTPUT ;
    USE SIGNAL ;
    PORT
      LAYER M5 ;
        RECT  43.392 0 43.416 0.192 ;
    END
  END o1[87]
  PIN o1[88]
    DIRECTION OUTPUT ;
    USE SIGNAL ;
    PORT
      LAYER M5 ;
        RECT  43.536 0 43.56 0.192 ;
    END
  END o1[88]
  PIN o1[89]
    DIRECTION OUTPUT ;
    USE SIGNAL ;
    PORT
      LAYER M5 ;
        RECT  43.728 0 43.752 0.192 ;
    END
  END o1[89]
  PIN o1[8]
    DIRECTION OUTPUT ;
    USE SIGNAL ;
    PORT
      LAYER M5 ;
        RECT  29.664 0 29.688 0.192 ;
    END
  END o1[8]
  PIN o1[90]
    DIRECTION OUTPUT ;
    USE SIGNAL ;
    PORT
      LAYER M5 ;
        RECT  43.92 0 43.944 0.192 ;
    END
  END o1[90]
  PIN o1[91]
    DIRECTION OUTPUT ;
    USE SIGNAL ;
    PORT
      LAYER M5 ;
        RECT  44.064 0 44.088 0.192 ;
    END
  END o1[91]
  PIN o1[92]
    DIRECTION OUTPUT ;
    USE SIGNAL ;
    PORT
      LAYER M5 ;
        RECT  44.256 0 44.28 0.192 ;
    END
  END o1[92]
  PIN o1[93]
    DIRECTION OUTPUT ;
    USE SIGNAL ;
    PORT
      LAYER M5 ;
        RECT  44.4 0 44.424 0.192 ;
    END
  END o1[93]
  PIN o1[94]
    DIRECTION OUTPUT ;
    USE SIGNAL ;
    PORT
      LAYER M5 ;
        RECT  44.592 0 44.616 0.192 ;
    END
  END o1[94]
  PIN o1[95]
    DIRECTION OUTPUT ;
    USE SIGNAL ;
    PORT
      LAYER M5 ;
        RECT  44.736 0 44.76 0.192 ;
    END
  END o1[95]
  PIN o1[96]
    DIRECTION OUTPUT ;
    USE SIGNAL ;
    PORT
      LAYER M5 ;
        RECT  44.928 0 44.952 0.192 ;
    END
  END o1[96]
  PIN o1[97]
    DIRECTION OUTPUT ;
    USE SIGNAL ;
    PORT
      LAYER M5 ;
        RECT  45.12 0 45.144 0.192 ;
    END
  END o1[97]
  PIN o1[98]
    DIRECTION OUTPUT ;
    USE SIGNAL ;
    PORT
      LAYER M5 ;
        RECT  45.264 0 45.288 0.192 ;
    END
  END o1[98]
  PIN o1[99]
    DIRECTION OUTPUT ;
    USE SIGNAL ;
    PORT
      LAYER M5 ;
        RECT  45.456 0 45.48 0.192 ;
    END
  END o1[99]
  PIN o1[9]
    DIRECTION OUTPUT ;
    USE SIGNAL ;
    PORT
      LAYER M5 ;
        RECT  29.808 0 29.832 0.192 ;
    END
  END o1[9]
  PIN rs
    DIRECTION INPUT ;
    USE SIGNAL ;
    PORT
      LAYER M4 ;
        RECT  0 10.8 0.192 10.824 ;
    END
    PORT
      LAYER M4 ;
        RECT  0.156 10.8 2.408 10.824 ;
    END
  END rs
  PIN VDD
    DIRECTION INOUT ;
    USE POWER ;
    PORT
      LAYER M5 ;
        RECT  53.892 2.151 54.012 19.449 ;
        RECT  51.192 2.151 51.312 19.449 ;
        RECT  48.492 2.151 48.612 19.449 ;
        RECT  45.792 2.151 45.912 19.449 ;
        RECT  43.092 2.151 43.212 19.449 ;
        RECT  40.392 2.151 40.512 19.449 ;
        RECT  37.692 2.151 37.812 19.449 ;
        RECT  34.992 2.151 35.112 19.449 ;
        RECT  32.292 2.151 32.412 19.449 ;
        RECT  29.592 2.151 29.712 19.449 ;
        RECT  26.892 2.151 27.012 19.449 ;
        RECT  24.192 2.151 24.312 19.449 ;
        RECT  21.492 2.151 21.612 19.449 ;
        RECT  18.792 2.151 18.912 19.449 ;
        RECT  16.092 2.151 16.212 19.449 ;
        RECT  13.392 2.151 13.512 19.449 ;
        RECT  10.692 2.151 10.812 19.449 ;
        RECT  7.992 2.151 8.112 19.449 ;
        RECT  5.292 2.151 5.412 19.449 ;
        RECT  2.592 2.151 2.712 19.449 ;
    END
  END VDD
  PIN VSS
    DIRECTION INOUT ;
    USE GROUND ;
    PORT
      LAYER M5 ;
        RECT  53.7 2.137 53.82 19.463 ;
        RECT  51 2.137 51.12 19.463 ;
        RECT  48.3 2.137 48.42 19.463 ;
        RECT  45.6 2.137 45.72 19.463 ;
        RECT  42.9 2.137 43.02 19.463 ;
        RECT  40.2 2.137 40.32 19.463 ;
        RECT  37.5 2.137 37.62 19.463 ;
        RECT  34.8 2.137 34.92 19.463 ;
        RECT  32.1 2.137 32.22 19.463 ;
        RECT  29.4 2.137 29.52 19.463 ;
        RECT  26.7 2.137 26.82 19.463 ;
        RECT  24 2.137 24.12 19.463 ;
        RECT  21.3 2.137 21.42 19.463 ;
        RECT  18.6 2.137 18.72 19.463 ;
        RECT  15.9 2.137 16.02 19.463 ;
        RECT  13.2 2.137 13.32 19.463 ;
        RECT  10.5 2.137 10.62 19.463 ;
        RECT  7.8 2.137 7.92 19.463 ;
        RECT  5.1 2.137 5.22 19.463 ;
        RECT  2.4 2.137 2.52 19.463 ;
    END
  END VSS
  # OT_OBS_CLOSED layer=M5 d_um=1.536 added=49
  OBS
    LAYER RVTN ;
     RECT  2.16 2.16 54 2.295 ;
     RECT  2.16 2.565 54 2.835 ;
     RECT  2.16 3.105 54 3.375 ;
     RECT  2.16 3.645 54 3.915 ;
     RECT  2.16 4.185 54 4.455 ;
     RECT  2.16 4.725 54 4.995 ;
     RECT  2.16 5.265 54 5.535 ;
     RECT  2.16 5.805 54 6.075 ;
     RECT  2.16 6.345 54 6.615 ;
     RECT  2.16 6.885 54 7.155 ;
     RECT  2.16 7.425 54 7.695 ;
     RECT  2.16 7.965 54 8.235 ;
     RECT  2.16 8.505 54 8.775 ;
     RECT  2.16 9.045 54 9.315 ;
     RECT  2.16 9.585 54 9.855 ;
     RECT  2.16 10.125 54 10.395 ;
     RECT  2.16 10.665 54 10.935 ;
     RECT  2.16 11.205 54 11.475 ;
     RECT  2.16 11.745 54 12.015 ;
     RECT  2.16 12.285 54 12.555 ;
     RECT  2.16 12.825 54 13.095 ;
     RECT  2.16 13.365 54 13.635 ;
     RECT  2.16 13.905 54 14.175 ;
     RECT  2.16 14.445 54 14.715 ;
     RECT  2.16 14.985 54 15.255 ;
     RECT  2.16 15.525 54 15.795 ;
     RECT  2.16 16.065 54 16.335 ;
     RECT  2.16 16.605 54 16.875 ;
     RECT  2.16 17.145 54 17.415 ;
     RECT  2.16 17.685 54 17.955 ;
     RECT  2.16 18.225 54 18.495 ;
     RECT  2.16 18.765 54 19.035 ;
     RECT  2.16 19.305 54 19.44 ;
    LAYER RVTP ;
     RECT  2.16 2.295 54 2.565 ;
     RECT  2.16 2.835 54 3.105 ;
     RECT  2.16 3.375 54 3.645 ;
     RECT  2.16 3.915 54 4.185 ;
     RECT  2.16 4.455 54 4.725 ;
     RECT  2.16 4.995 54 5.265 ;
     RECT  2.16 5.535 54 5.805 ;
     RECT  2.16 6.075 54 6.345 ;
     RECT  2.16 6.615 54 6.885 ;
     RECT  2.16 7.155 54 7.425 ;
     RECT  2.16 7.695 54 7.965 ;
     RECT  2.16 8.235 54 8.505 ;
     RECT  2.16 8.775 54 9.045 ;
     RECT  2.16 9.315 54 9.585 ;
     RECT  2.16 9.855 54 10.125 ;
     RECT  2.16 10.395 54 10.665 ;
     RECT  2.16 10.935 54 11.205 ;
     RECT  2.16 11.475 54 11.745 ;
     RECT  2.16 12.015 54 12.285 ;
     RECT  2.16 12.555 54 12.825 ;
     RECT  2.16 13.095 54 13.365 ;
     RECT  2.16 13.635 54 13.905 ;
     RECT  2.16 14.175 54 14.445 ;
     RECT  2.16 14.715 54 14.985 ;
     RECT  2.16 15.255 54 15.525 ;
     RECT  2.16 15.795 54 16.065 ;
     RECT  2.16 16.335 54 16.605 ;
     RECT  2.16 16.875 54 17.145 ;
     RECT  2.16 17.415 54 17.685 ;
     RECT  2.16 17.955 54 18.225 ;
     RECT  2.16 18.495 54 18.765 ;
     RECT  2.16 19.035 54 19.305 ;
    LAYER M1 ;
     RECT  2.16 2.151 54 19.449 ;
    LAYER M2 ;
     RECT  2.16 2.151 6.547 19.449 ;
     RECT  6.547 2.106 10.283 19.449 ;
     RECT  10.283 2.151 11.767 19.449 ;
     RECT  17.059 0.576 17.375 0.594 ;
     RECT  11.767 1.566 17.923 19.449 ;
     RECT  17.923 0.846 21.379 19.449 ;
     RECT  21.379 0.576 22.559 19.449 ;
     RECT  24.439 0.036 24.655 0.054 ;
     RECT  22.559 0.882 25.123 19.449 ;
     RECT  24.655 0.036 29.227 0.09 ;
     RECT  25.123 0.846 29.227 19.449 ;
     RECT  29.227 0.036 35.951 19.449 ;
     RECT  35.951 0.072 36.131 19.449 ;
     RECT  36.131 0.108 38.219 19.449 ;
     RECT  38.219 0.846 46.463 19.449 ;
     RECT  46.463 0.846 47.471 0.864 ;
     RECT  46.463 1.764 47.759 19.449 ;
     RECT  47.759 1.998 48.659 19.449 ;
     RECT  48.659 2.151 54 19.449 ;
     RECT  54 2.421 54.012 19.179 ;
    LAYER M3 ;
     RECT  24.444 0.031 24.462 0.067 ;
     RECT  35.928 0.031 35.946 0.067 ;
     RECT  24.444 0.067 24.678 0.091 ;
     RECT  28.728 0.043 28.746 0.103 ;
     RECT  17.136 0.043 17.154 0.139 ;
     RECT  24.336 0.091 24.678 0.139 ;
     RECT  35.928 0.067 36.126 0.139 ;
     RECT  23.364 0.091 23.382 0.187 ;
     RECT  24.336 0.139 25.002 0.187 ;
     RECT  28.728 0.103 29.25 0.187 ;
     RECT  31.536 0.043 31.554 0.187 ;
     RECT  35.928 0.139 36.522 0.187 ;
     RECT  38.196 0.103 38.214 0.187 ;
     RECT  37.872 0.187 38.214 0.221 ;
     RECT  35.676 0.187 36.522 0.235 ;
     RECT  16.524 0.139 17.154 0.269 ;
     RECT  35.46 0.235 36.522 0.269 ;
     RECT  32.94 0.187 32.958 0.283 ;
     RECT  18.828 0.187 18.846 0.317 ;
     RECT  31.212 0.187 31.554 0.328 ;
     RECT  26.784 0.187 26.802 0.365 ;
     RECT  28.26 0.187 29.25 0.379 ;
     RECT  46.476 0.187 46.494 0.475 ;
     RECT  29.988 0.187 30.006 0.523 ;
     RECT  31.032 0.328 31.554 0.523 ;
     RECT  32.868 0.283 32.958 0.523 ;
     RECT  35.46 0.269 35.982 0.523 ;
     RECT  37.872 0.221 37.89 0.523 ;
     RECT  6.876 0.187 6.894 0.571 ;
     RECT  8.244 0.187 8.262 0.571 ;
     RECT  9 0.187 9.018 0.571 ;
     RECT  17.064 0.269 17.154 0.571 ;
     RECT  17.928 0.235 17.946 0.571 ;
     RECT  21.384 0.187 25.902 0.571 ;
     RECT  27.756 0.379 29.25 0.571 ;
     RECT  29.988 0.523 30.114 0.571 ;
     RECT  41.364 0.187 41.994 0.571 ;
     RECT  45.468 0.523 45.486 0.571 ;
     RECT  46.332 0.475 46.494 0.571 ;
     RECT  48.276 0.523 48.294 0.571 ;
     RECT  17.064 0.571 17.982 0.599 ;
     RECT  27.72 0.571 30.114 0.763 ;
     RECT  43.308 0.523 43.902 0.811 ;
     RECT  21.384 0.571 25.938 0.841 ;
     RECT  41.148 0.571 42.318 0.859 ;
     RECT  43.308 0.811 44.442 0.859 ;
     RECT  37.656 0.523 37.89 0.907 ;
     RECT  38.88 0.913 38.898 0.949 ;
     RECT  14.832 0.043 14.85 0.955 ;
     RECT  20.844 0.841 25.938 0.955 ;
     RECT  38.88 0.949 38.934 0.985 ;
     RECT  49.212 0.571 49.23 1.003 ;
     RECT  32.868 0.523 34.29 1.051 ;
     RECT  35.424 0.523 35.982 1.051 ;
     RECT  50.904 0.187 51.174 1.051 ;
     RECT  5.256 0.571 5.742 1.099 ;
     RECT  6.696 0.571 6.894 1.099 ;
     RECT  8.244 0.571 9.018 1.099 ;
     RECT  37.008 0.907 37.89 1.099 ;
     RECT  38.808 0.985 38.934 1.099 ;
     RECT  39.672 0.955 39.69 1.099 ;
     RECT  41.148 0.859 44.442 1.099 ;
     RECT  45.468 0.571 46.494 1.099 ;
     RECT  47.304 0.571 48.294 1.099 ;
     RECT  5.256 1.099 6.894 1.147 ;
     RECT  7.704 1.099 9.018 1.147 ;
     RECT  13.176 0.907 13.194 1.147 ;
     RECT  32.868 1.051 35.982 1.147 ;
     RECT  20.772 0.955 25.938 1.175 ;
     RECT  27.72 0.763 30.222 1.195 ;
     RECT  30.96 0.523 31.554 1.195 ;
     RECT  19.836 1.051 19.854 1.483 ;
     RECT  40.788 1.099 46.494 1.489 ;
     RECT  32.472 1.147 35.982 1.531 ;
     RECT  27.72 1.195 31.554 1.579 ;
     RECT  32.292 1.531 35.982 1.579 ;
     RECT  37.008 1.099 39.69 1.675 ;
     RECT  40.644 1.489 46.494 1.675 ;
     RECT  47.304 1.099 48.474 1.675 ;
     RECT  49.212 1.003 49.77 1.675 ;
     RECT  4.68 1.147 6.894 1.723 ;
     RECT  7.704 1.147 9.558 1.723 ;
     RECT  11.772 1.561 11.79 1.723 ;
     RECT  13.176 1.147 13.374 1.723 ;
     RECT  14.832 0.955 15.102 1.723 ;
     RECT  19.692 1.483 19.854 1.723 ;
     RECT  27.72 1.579 35.982 1.723 ;
     RECT  47.304 1.675 49.77 1.723 ;
     RECT  50.508 1.051 51.174 1.723 ;
     RECT  21.672 1.175 25.938 1.759 ;
     RECT  26.748 1.723 35.982 1.759 ;
     RECT  11.772 1.723 15.102 1.771 ;
     RECT  16.164 1.723 16.182 1.771 ;
     RECT  4.536 1.723 10.206 1.819 ;
     RECT  17.136 0.599 17.982 1.921 ;
     RECT  11.772 1.771 16.182 1.957 ;
     RECT  17.028 1.921 17.982 1.957 ;
     RECT  19.656 1.723 19.854 1.993 ;
     RECT  20.772 1.175 20.862 1.993 ;
     RECT  21.672 1.759 35.982 1.993 ;
     RECT  4.536 1.819 10.242 2.011 ;
     RECT  18.828 1.993 19.854 2.065 ;
     RECT  20.772 1.993 35.982 2.065 ;
     RECT  4.536 2.011 10.35 2.143 ;
     RECT  11.772 1.957 17.982 2.143 ;
     RECT  18.828 2.065 36.054 2.143 ;
     RECT  53.028 1.723 53.046 2.143 ;
     RECT  37.008 1.675 46.494 2.191 ;
     RECT  47.304 1.723 51.174 2.191 ;
     RECT  11.772 2.143 36.054 2.219 ;
     RECT  4.536 2.143 10.605 2.227 ;
     RECT  11.916 2.219 36.054 2.263 ;
     RECT  37.008 2.191 51.174 2.263 ;
     RECT  53.028 2.143 53.805 2.335 ;
     RECT  2.415 2.143 2.505 2.413 ;
     RECT  36.936 2.263 51.174 2.413 ;
     RECT  52.884 2.335 53.805 2.413 ;
     RECT  4.536 2.227 10.854 2.461 ;
     RECT  4.536 2.461 10.926 2.596 ;
     RECT  4.536 2.596 10.962 2.641 ;
     RECT  4.14 2.641 10.962 2.759 ;
     RECT  36.936 2.413 51.297 2.803 ;
     RECT  52.884 2.413 53.997 2.875 ;
     RECT  52.812 2.875 53.997 2.911 ;
     RECT  36.936 2.803 51.894 3.029 ;
     RECT  52.632 2.911 53.997 3.029 ;
     RECT  11.916 2.263 36.162 3.037 ;
     RECT  36.936 3.029 51.786 3.037 ;
     RECT  11.916 3.037 51.786 3.065 ;
     RECT  17.028 3.065 51.786 3.299 ;
     RECT  4.536 2.759 10.854 3.613 ;
     RECT  11.916 3.065 16.218 3.613 ;
     RECT  4.536 3.613 16.218 3.955 ;
     RECT  17.028 3.299 19.998 3.955 ;
     RECT  4.536 3.955 19.998 4.117 ;
     RECT  20.736 3.299 35.694 4.117 ;
     RECT  4.536 4.117 35.694 4.123 ;
     RECT  36.468 3.299 51.786 4.123 ;
     RECT  4.536 4.123 51.786 4.261 ;
     RECT  52.632 3.029 52.83 4.261 ;
     RECT  4.536 4.261 52.83 4.289 ;
     RECT  4.536 4.289 8.262 4.379 ;
     RECT  9 4.289 52.83 4.379 ;
     RECT  52.344 4.379 52.83 4.531 ;
     RECT  53.715 3.029 53.997 4.531 ;
     RECT  52.344 4.531 53.997 4.559 ;
     RECT  4.752 4.379 8.262 4.649 ;
     RECT  9 4.379 51.39 4.991 ;
     RECT  5.04 4.649 8.262 5.035 ;
     RECT  9 4.991 19.998 5.035 ;
     RECT  20.772 4.991 51.39 5.341 ;
     RECT  5.04 5.035 19.998 5.369 ;
     RECT  20.772 5.341 51.714 5.639 ;
     RECT  5.115 5.369 19.998 5.971 ;
     RECT  20.772 5.639 27.126 5.971 ;
     RECT  5.115 5.971 27.126 6.107 ;
     RECT  6.12 6.107 27.126 6.421 ;
     RECT  27.9 5.639 51.714 6.421 ;
     RECT  6.12 6.421 51.714 8.429 ;
     RECT  2.415 2.413 2.697 10.795 ;
     RECT  2.304 10.795 2.697 11.975 ;
     RECT  2.376 11.975 2.697 13.055 ;
     RECT  2.415 13.055 2.697 14.215 ;
     RECT  2.415 14.215 2.898 14.945 ;
     RECT  4.356 14.881 4.374 15.061 ;
     RECT  5.115 6.107 5.397 15.061 ;
     RECT  3.492 15.061 3.51 15.331 ;
     RECT  4.356 15.061 5.397 15.331 ;
     RECT  3.492 15.331 5.397 15.485 ;
     RECT  3.996 15.485 5.397 15.529 ;
     RECT  6.12 8.429 49.338 15.529 ;
     RECT  2.415 14.945 2.697 15.829 ;
     RECT  3.996 15.529 49.338 15.863 ;
     RECT  2.415 15.829 3.186 15.869 ;
     RECT  4.356 15.863 49.338 16.295 ;
     RECT  4.932 16.295 49.338 16.411 ;
     RECT  50.076 8.429 51.714 16.411 ;
     RECT  4.932 16.411 51.714 16.529 ;
     RECT  5.115 16.529 51.714 16.915 ;
     RECT  52.632 4.559 53.997 16.915 ;
     RECT  5.115 16.915 53.997 17.339 ;
     RECT  5.115 17.339 52.686 17.995 ;
     RECT  4.86 17.995 52.686 18.031 ;
     RECT  4.824 18.031 52.686 18.121 ;
     RECT  4.644 18.121 52.686 18.173 ;
     RECT  4.68 18.173 52.686 18.419 ;
     RECT  4.68 18.419 52.29 18.689 ;
     RECT  4.68 18.689 51.858 18.959 ;
     RECT  4.68 18.959 51.786 19.075 ;
     RECT  2.415 15.869 2.697 19.187 ;
     RECT  53.715 17.339 53.997 19.187 ;
     RECT  4.572 19.075 51.786 19.229 ;
     RECT  4.572 19.229 51.714 19.265 ;
     RECT  4.572 19.265 25.074 19.339 ;
     RECT  4.536 19.339 25.074 19.379 ;
     RECT  25.992 19.265 38.502 19.379 ;
     RECT  39.24 19.265 51.714 19.379 ;
     RECT  2.415 19.187 2.505 19.457 ;
     RECT  5.115 19.379 5.274 19.457 ;
     RECT  7.815 19.379 8.01 19.457 ;
     RECT  18.615 19.379 18.774 19.457 ;
     RECT  21.315 19.379 21.546 19.457 ;
     RECT  24.015 19.379 24.282 19.457 ;
     RECT  29.415 19.379 29.574 19.457 ;
     RECT  32.115 19.379 32.274 19.457 ;
     RECT  34.815 19.379 35.01 19.457 ;
     RECT  42.915 19.379 43.074 19.457 ;
     RECT  45.615 19.379 45.774 19.457 ;
     RECT  48.315 19.379 48.546 19.457 ;
     RECT  53.715 19.187 53.805 19.457 ;
     RECT  7.992 19.457 8.01 19.565 ;
     RECT  10.44 19.379 10.782 19.565 ;
     RECT  13.176 19.379 13.554 19.565 ;
     RECT  15.876 19.379 16.29 19.565 ;
     RECT  21.528 19.457 21.546 19.565 ;
     RECT  24.264 19.457 24.282 19.565 ;
     RECT  26.676 19.379 27.054 19.565 ;
     RECT  34.992 19.457 35.01 19.565 ;
     RECT  37.44 19.379 37.818 19.565 ;
     RECT  40.176 19.379 40.59 19.565 ;
     RECT  48.528 19.457 48.546 19.565 ;
     RECT  50.94 19.379 51.282 19.565 ;
     RECT  5.256 19.457 5.274 19.613 ;
     RECT  13.176 19.565 13.194 19.613 ;
     RECT  15.876 19.565 15.894 19.613 ;
     RECT  18.756 19.457 18.774 19.613 ;
     RECT  26.676 19.565 26.694 19.613 ;
     RECT  29.556 19.457 29.574 19.613 ;
     RECT  32.256 19.457 32.274 19.613 ;
     RECT  37.44 19.565 37.458 19.613 ;
     RECT  40.176 19.565 40.194 19.613 ;
     RECT  43.056 19.457 43.074 19.613 ;
     RECT  45.756 19.457 45.774 19.613 ;
    LAYER M4 ;
     RECT  2.408 2.148 2.512 19.452 ;
     RECT  2.512 2.418 2.704 19.182 ;
     RECT  2.704 15.84 4.076 15.864 ;
     RECT  4.076 15.36 4.117 15.864 ;
     RECT  4.481 1.728 4.625 1.752 ;
     RECT  4.625 1.152 4.709 1.752 ;
     RECT  4.709 1.728 4.988 1.752 ;
     RECT  4.988 1.728 5.108 2.04 ;
     RECT  4.117 15.36 5.108 16.008 ;
     RECT  4.633 18.144 5.108 18.168 ;
     RECT  4.501 19.344 5.108 19.368 ;
     RECT  5.108 1.728 5.173 19.452 ;
     RECT  5.173 1.728 5.285 19.608 ;
     RECT  5.173 0.576 5.365 0.6 ;
     RECT  5.285 1.728 5.404 19.368 ;
     RECT  5.365 0.288 5.603 0.6 ;
     RECT  5.603 0.576 5.893 0.6 ;
     RECT  5.404 1.728 5.893 1.8 ;
     RECT  5.404 5.136 6.329 5.16 ;
     RECT  5.404 16.896 6.365 18.216 ;
     RECT  5.893 0.576 6.419 1.8 ;
     RECT  5.404 19.344 6.524 19.368 ;
     RECT  6.524 18.816 6.611 19.368 ;
     RECT  6.419 0.576 6.725 0.6 ;
     RECT  6.865 0.192 6.949 0.216 ;
     RECT  6.419 1.728 7.693 1.8 ;
     RECT  7.693 1.104 7.765 1.8 ;
     RECT  7.093 2.88 7.765 2.904 ;
     RECT  7.765 1.104 7.808 2.904 ;
     RECT  6.793 4.128 7.808 4.152 ;
     RECT  6.365 16.896 7.808 17.784 ;
     RECT  6.611 19.344 7.808 19.368 ;
     RECT  7.808 1.104 7.811 19.452 ;
     RECT  7.811 1.728 7.957 19.452 ;
     RECT  7.957 1.728 8.044 19.56 ;
     RECT  8.044 1.728 8.104 19.368 ;
     RECT  8.104 2.88 8.237 2.904 ;
     RECT  8.101 0.192 8.489 0.6 ;
     RECT  8.104 5.712 8.597 5.736 ;
     RECT  8.104 16.752 8.849 17.688 ;
     RECT  8.849 16.752 8.885 17.112 ;
     RECT  8.489 0.192 9.029 0.216 ;
     RECT  8.104 1.728 9.485 1.8 ;
     RECT  9.485 1.152 9.569 1.8 ;
     RECT  9.569 1.728 9.596 1.8 ;
     RECT  9.157 5.136 9.829 5.16 ;
     RECT  8.885 17.088 9.853 17.112 ;
     RECT  9.853 17.088 10.22 17.448 ;
     RECT  10.22 16.512 10.261 17.448 ;
     RECT  8.104 18.816 10.261 19.368 ;
     RECT  9.829 5.136 10.357 5.208 ;
     RECT  10.261 16.512 10.405 19.368 ;
     RECT  9.596 1.728 10.508 2.28 ;
     RECT  8.104 4.128 10.508 4.152 ;
     RECT  10.357 5.136 10.508 5.496 ;
     RECT  10.405 16.512 10.508 19.56 ;
     RECT  10.508 1.728 10.804 19.56 ;
     RECT  10.804 16.368 10.828 19.56 ;
     RECT  10.804 5.136 11.081 6.312 ;
     RECT  10.597 0.048 11.173 0.216 ;
     RECT  10.804 1.728 11.173 1.848 ;
     RECT  10.804 4.128 12.121 4.152 ;
     RECT  11.081 5.136 12.121 5.736 ;
     RECT  10.828 16.368 12.125 19.368 ;
     RECT  12.121 4.128 12.233 5.736 ;
     RECT  11.173 0.048 12.38 1.848 ;
     RECT  12.125 19.344 13.141 19.368 ;
     RECT  12.38 0.048 13.208 2.28 ;
     RECT  12.233 4.128 13.208 5.592 ;
     RECT  12.125 16.368 13.208 18.168 ;
     RECT  13.141 19.344 13.208 19.608 ;
     RECT  13.208 0.048 13.228 19.608 ;
     RECT  13.228 0.048 13.504 19.56 ;
     RECT  13.504 19.344 13.571 19.56 ;
     RECT  13.504 16.368 13.619 17.112 ;
     RECT  13.504 4.128 14.629 4.152 ;
     RECT  13.619 16.512 14.821 17.112 ;
     RECT  13.504 0.048 14.861 2.328 ;
     RECT  14.861 0.096 14.965 2.328 ;
     RECT  14.629 3.312 14.965 4.152 ;
     RECT  13.571 19.344 15.865 19.368 ;
     RECT  14.965 0.096 15.908 4.152 ;
     RECT  14.821 16.368 15.908 17.112 ;
     RECT  13.504 18.144 15.908 18.168 ;
     RECT  15.865 19.344 15.908 19.608 ;
     RECT  15.908 0.096 15.971 19.608 ;
     RECT  15.971 0.096 16.204 19.56 ;
     RECT  16.204 19.344 16.307 19.56 ;
     RECT  16.204 0.096 17.125 4.152 ;
     RECT  17.125 0.048 17.201 4.152 ;
     RECT  17.201 3.312 17.221 4.152 ;
     RECT  17.221 3.312 17.557 4.248 ;
     RECT  16.204 5.472 17.557 5.832 ;
     RECT  17.201 0.048 18.421 2.28 ;
     RECT  17.557 3.312 18.421 5.832 ;
     RECT  18.421 0.048 18.608 5.832 ;
     RECT  16.204 16.368 18.608 16.392 ;
     RECT  16.204 17.472 18.608 18.024 ;
     RECT  16.307 19.344 18.608 19.368 ;
     RECT  18.608 0.048 18.709 19.452 ;
     RECT  18.709 0.048 18.796 19.608 ;
     RECT  18.796 0.048 18.904 19.368 ;
     RECT  18.904 0.048 19.001 5.832 ;
     RECT  19.001 0.048 19.973 5.592 ;
     RECT  19.973 0.048 21.308 5.544 ;
     RECT  20.965 6.912 21.308 6.936 ;
     RECT  18.904 16.368 21.308 19.368 ;
     RECT  21.308 0.048 21.493 19.452 ;
     RECT  21.493 0.048 21.58 19.56 ;
     RECT  21.58 0.048 21.604 19.368 ;
     RECT  21.604 16.368 21.731 19.368 ;
     RECT  21.731 16.512 22.169 19.368 ;
     RECT  21.604 0.048 22.813 5.736 ;
     RECT  22.169 16.512 22.813 16.872 ;
     RECT  21.604 7.056 22.853 7.896 ;
     RECT  22.813 0.048 23.101 5.832 ;
     RECT  22.813 16.368 23.173 16.872 ;
     RECT  22.169 17.952 23.173 19.368 ;
     RECT  23.101 0.048 23.221 5.88 ;
     RECT  22.853 7.056 23.221 7.752 ;
     RECT  23.221 0.048 24.008 7.752 ;
     RECT  23.173 16.368 24.008 19.368 ;
     RECT  24.008 0.048 24.229 19.452 ;
     RECT  24.229 0.048 24.304 19.56 ;
     RECT  24.304 17.472 24.316 19.56 ;
     RECT  24.316 17.472 24.419 19.368 ;
     RECT  24.419 17.472 24.617 17.496 ;
     RECT  24.304 16.368 25.297 16.392 ;
     RECT  24.419 18.816 25.729 19.368 ;
     RECT  25.297 16.368 26.341 16.968 ;
     RECT  25.729 18.192 26.341 19.368 ;
     RECT  26.341 16.368 26.636 19.368 ;
     RECT  24.304 0.048 26.708 7.752 ;
     RECT  26.636 16.368 26.708 19.608 ;
     RECT  26.708 0.048 26.723 19.608 ;
     RECT  26.723 0.048 27.004 19.56 ;
     RECT  27.004 19.344 27.1 19.56 ;
     RECT  27.004 0.048 28.757 7.752 ;
     RECT  27.004 16.368 28.969 16.536 ;
     RECT  27.004 17.664 28.969 17.688 ;
     RECT  28.757 0.096 29.408 7.752 ;
     RECT  28.969 16.368 29.408 17.688 ;
     RECT  27.1 19.344 29.408 19.368 ;
     RECT  29.408 0.096 29.461 19.452 ;
     RECT  29.461 0.096 29.585 19.608 ;
     RECT  29.585 0.096 29.704 19.368 ;
     RECT  29.704 16.368 29.843 18.168 ;
     RECT  29.704 0.096 30.809 7.896 ;
     RECT  29.843 16.512 30.809 18.168 ;
     RECT  30.809 16.512 30.841 16.968 ;
     RECT  30.809 0.096 31.525 7.752 ;
     RECT  30.809 18 31.669 18.168 ;
     RECT  29.704 19.344 31.669 19.368 ;
     RECT  30.841 16.368 31.957 16.968 ;
     RECT  31.669 18 31.957 19.368 ;
     RECT  31.525 0.048 32.108 7.752 ;
     RECT  31.957 16.368 32.108 19.368 ;
     RECT  32.108 0.048 32.197 19.452 ;
     RECT  32.197 0.048 32.285 19.608 ;
     RECT  32.285 0.048 32.404 19.368 ;
     RECT  32.404 16.368 33.148 19.368 ;
     RECT  32.404 14.832 33.257 14.856 ;
     RECT  33.148 16.368 33.725 17.64 ;
     RECT  33.148 18.816 34.364 19.368 ;
     RECT  33.725 16.368 34.405 16.536 ;
     RECT  33.725 17.52 34.405 17.64 ;
     RECT  34.364 18.672 34.405 19.368 ;
     RECT  32.404 0.048 34.808 7.752 ;
     RECT  34.405 16.272 34.808 16.536 ;
     RECT  34.405 17.52 34.808 19.368 ;
     RECT  34.808 0.048 34.94 19.452 ;
     RECT  34.94 0.048 35.027 19.56 ;
     RECT  35.027 0.048 35.104 19.368 ;
     RECT  35.104 17.616 35.219 19.368 ;
     RECT  35.104 16.272 35.849 16.536 ;
     RECT  35.849 16.512 35.891 16.536 ;
     RECT  35.219 18.192 36.205 19.368 ;
     RECT  35.104 3.648 36.227 7.752 ;
     RECT  36.205 17.616 36.565 19.368 ;
     RECT  35.104 0.048 37.033 2.28 ;
     RECT  36.227 3.648 37.033 4.152 ;
     RECT  36.565 16.8 37.388 19.368 ;
     RECT  37.388 16.8 37.475 19.608 ;
     RECT  37.033 0.048 37.508 4.152 ;
     RECT  36.227 5.808 37.508 7.752 ;
     RECT  37.475 16.8 37.508 19.56 ;
     RECT  37.508 0.048 37.804 19.56 ;
     RECT  37.804 16.8 37.852 19.56 ;
     RECT  37.804 0.048 37.901 4.152 ;
     RECT  37.804 5.808 38.405 7.896 ;
     RECT  38.405 6.528 38.621 7.896 ;
     RECT  38.621 6.528 38.801 6.648 ;
     RECT  37.852 16.8 39.053 19.368 ;
     RECT  37.901 0.048 39.395 3.672 ;
     RECT  39.395 0.192 39.827 3.672 ;
     RECT  39.053 17.952 40.124 19.368 ;
     RECT  39.827 0.288 40.208 3.672 ;
     RECT  38.801 6.624 40.208 6.648 ;
     RECT  38.621 7.872 40.208 7.896 ;
     RECT  39.053 16.8 40.208 16.824 ;
     RECT  40.124 17.952 40.208 19.608 ;
     RECT  40.208 0.288 40.211 19.608 ;
     RECT  40.211 0.288 40.504 19.56 ;
     RECT  40.504 17.04 40.636 19.56 ;
     RECT  40.504 3.408 40.643 4.2 ;
     RECT  40.643 3.648 40.691 4.2 ;
     RECT  40.504 0.288 41.027 2.28 ;
     RECT  41.027 0.288 41.309 1.752 ;
     RECT  41.309 0.192 42.049 1.752 ;
     RECT  40.636 17.04 42.181 19.368 ;
     RECT  42.049 0.576 42.505 1.752 ;
     RECT  42.181 16.896 42.757 19.368 ;
     RECT  42.505 0.576 42.908 2.28 ;
     RECT  40.691 3.648 42.908 3.672 ;
     RECT  40.504 6.624 42.908 6.648 ;
     RECT  42.757 16.368 42.908 19.368 ;
     RECT  42.908 0.576 42.949 19.452 ;
     RECT  42.949 0.576 43.012 19.608 ;
     RECT  43.012 2.418 43.085 19.608 ;
     RECT  43.012 0.576 43.189 1.416 ;
     RECT  43.085 2.418 43.204 19.368 ;
     RECT  43.189 0.192 43.331 1.416 ;
     RECT  43.204 16.368 43.811 19.368 ;
     RECT  43.331 0.528 43.955 1.416 ;
     RECT  43.955 0.816 44.233 1.416 ;
     RECT  43.204 2.544 44.233 3.672 ;
     RECT  44.233 0.816 44.317 3.672 ;
     RECT  44.317 0.816 44.453 1.128 ;
     RECT  44.317 2.256 44.489 3.672 ;
     RECT  43.811 16.368 44.525 18.264 ;
     RECT  44.525 16.512 45.097 18.264 ;
     RECT  43.811 19.344 45.097 19.368 ;
     RECT  44.453 1.104 45.457 1.128 ;
     RECT  45.097 16.512 45.493 19.368 ;
     RECT  45.457 0.528 45.565 1.128 ;
     RECT  44.489 2.256 45.608 3.432 ;
     RECT  45.493 16.368 45.608 19.368 ;
     RECT  45.608 2.148 45.733 19.452 ;
     RECT  45.733 2.148 45.82 19.608 ;
     RECT  45.82 2.148 45.904 19.368 ;
     RECT  45.565 0.528 45.925 1.176 ;
     RECT  45.904 2.148 45.925 2.904 ;
     RECT  45.925 0.528 46.009 2.904 ;
     RECT  46.009 0.528 46.321 1.176 ;
     RECT  46.321 0.48 46.421 1.176 ;
     RECT  46.421 0.192 46.505 1.176 ;
     RECT  46.505 0.48 46.835 1.176 ;
     RECT  46.009 2.832 46.933 2.904 ;
     RECT  46.933 2.832 47.027 3.432 ;
     RECT  45.904 15.984 47.045 19.368 ;
     RECT  47.027 2.832 47.329 2.856 ;
     RECT  46.835 0.48 47.555 0.6 ;
     RECT  47.329 2.256 48.049 2.856 ;
     RECT  48.049 1.728 48.308 2.856 ;
     RECT  47.045 15.984 48.308 16.008 ;
     RECT  47.045 17.04 48.308 19.368 ;
     RECT  47.555 0.528 48.419 0.6 ;
     RECT  48.419 0.576 48.445 0.6 ;
     RECT  48.308 1.728 48.445 19.452 ;
     RECT  48.445 0.576 48.476 19.452 ;
     RECT  48.476 0.576 48.563 19.56 ;
     RECT  48.563 1.68 48.604 19.368 ;
     RECT  48.604 3.984 49.091 4.008 ;
     RECT  48.563 0.576 49.241 0.6 ;
     RECT  48.604 5.712 49.637 5.736 ;
     RECT  48.604 1.68 49.676 1.752 ;
     RECT  49.676 1.008 50.627 1.752 ;
     RECT  48.604 17.088 50.869 19.368 ;
     RECT  50.869 16.944 50.917 19.368 ;
     RECT  50.773 0.192 50.969 0.6 ;
     RECT  50.627 1.728 51.008 1.752 ;
     RECT  50.917 16.944 51.008 19.56 ;
     RECT  50.969 0.192 51.185 0.216 ;
     RECT  51.008 1.728 51.299 19.56 ;
     RECT  51.299 1.728 51.304 19.368 ;
     RECT  51.304 18.48 51.401 19.368 ;
     RECT  51.401 19.344 51.725 19.368 ;
     RECT  51.304 17.472 51.833 17.496 ;
     RECT  51.304 1.728 53.057 1.752 ;
     RECT  51.304 2.88 53.708 2.904 ;
     RECT  53.708 2.148 53.812 19.452 ;
     RECT  53.812 2.418 54.004 19.182 ;
    LAYER M5 ;
     RECT  10.608 0.037 10.632 0.144 ;
     RECT  15.072 0.085 15.096 0.144 ;
     RECT  35.568 0.085 35.592 0.144 ;
     RECT  39.36 0.037 39.384 0.144 ;
     RECT  4.536 0.144 4.656 0.192 ;
     RECT  4.68 0.144 4.848 0.192 ;
     RECT  4.872 0.144 5.04 0.192 ;
     RECT  5.064 0.144 5.184 0.192 ;
     RECT  5.208 0.144 5.376 0.192 ;
     RECT  5.4 0.144 5.52 0.192 ;
     RECT  5.544 0.144 5.712 0.192 ;
     RECT  5.736 0.144 5.904 0.192 ;
     RECT  5.928 0.144 6.048 0.192 ;
     RECT  6.072 0.144 6.24 0.192 ;
     RECT  6.264 0.144 6.384 0.192 ;
     RECT  6.408 0.144 6.576 0.192 ;
     RECT  6.6 0.144 6.72 0.192 ;
     RECT  6.744 0.144 6.912 0.192 ;
     RECT  6.936 0.144 7.104 0.192 ;
     RECT  7.128 0.144 7.248 0.192 ;
     RECT  7.272 0.144 7.44 0.192 ;
     RECT  7.464 0.144 7.584 0.192 ;
     RECT  7.608 0.144 7.776 0.192 ;
     RECT  7.8 0.144 7.92 0.192 ;
     RECT  7.944 0.144 8.112 0.192 ;
     RECT  8.136 0.144 8.304 0.192 ;
     RECT  8.328 0.144 8.448 0.192 ;
     RECT  8.472 0.144 8.64 0.192 ;
     RECT  8.664 0.144 8.784 0.192 ;
     RECT  8.808 0.144 8.976 0.192 ;
     RECT  9 0.144 9.168 0.192 ;
     RECT  9.192 0.144 9.312 0.192 ;
     RECT  9.336 0.144 9.504 0.192 ;
     RECT  9.528 0.144 9.648 0.192 ;
     RECT  9.672 0.144 9.84 0.192 ;
     RECT  9.864 0.144 9.984 0.192 ;
     RECT  10.008 0.144 10.176 0.192 ;
     RECT  10.2 0.144 10.368 0.192 ;
     RECT  10.392 0.144 10.512 0.192 ;
     RECT  10.536 0.144 10.704 0.192 ;
     RECT  10.728 0.144 10.848 0.192 ;
     RECT  10.872 0.144 11.04 0.192 ;
     RECT  11.064 0.144 11.184 0.192 ;
     RECT  11.208 0.144 11.376 0.192 ;
     RECT  11.4 0.144 11.568 0.192 ;
     RECT  11.592 0.144 11.712 0.192 ;
     RECT  11.736 0.144 11.904 0.192 ;
     RECT  11.928 0.144 12.048 0.192 ;
     RECT  12.072 0.144 12.24 0.192 ;
     RECT  12.264 0.144 12.432 0.192 ;
     RECT  12.456 0.144 12.576 0.192 ;
     RECT  12.6 0.144 12.768 0.192 ;
     RECT  12.792 0.144 12.912 0.192 ;
     RECT  12.936 0.144 13.104 0.192 ;
     RECT  13.128 0.144 13.248 0.192 ;
     RECT  13.272 0.144 13.44 0.192 ;
     RECT  13.464 0.144 13.632 0.192 ;
     RECT  13.656 0.144 13.776 0.192 ;
     RECT  13.8 0.144 13.968 0.192 ;
     RECT  13.992 0.144 14.112 0.192 ;
     RECT  14.136 0.144 14.304 0.192 ;
     RECT  14.328 0.144 14.448 0.192 ;
     RECT  14.472 0.144 14.64 0.192 ;
     RECT  14.664 0.144 14.832 0.192 ;
     RECT  14.856 0.144 14.976 0.192 ;
     RECT  15 0.144 15.168 0.192 ;
     RECT  15.192 0.144 15.312 0.192 ;
     RECT  15.336 0.144 15.504 0.192 ;
     RECT  15.528 0.144 15.696 0.192 ;
     RECT  15.72 0.144 15.84 0.192 ;
     RECT  15.864 0.144 16.032 0.192 ;
     RECT  16.056 0.144 16.176 0.192 ;
     RECT  16.2 0.144 16.368 0.192 ;
     RECT  16.392 0.144 16.512 0.192 ;
     RECT  16.536 0.144 16.704 0.192 ;
     RECT  16.728 0.144 16.896 0.192 ;
     RECT  16.92 0.144 17.04 0.192 ;
     RECT  17.064 0.144 17.232 0.192 ;
     RECT  17.256 0.144 17.376 0.192 ;
     RECT  17.4 0.144 17.568 0.192 ;
     RECT  17.592 0.144 17.712 0.192 ;
     RECT  17.736 0.144 17.904 0.192 ;
     RECT  17.928 0.144 18.096 0.192 ;
     RECT  18.12 0.144 18.24 0.192 ;
     RECT  18.264 0.144 18.432 0.192 ;
     RECT  18.456 0.144 18.576 0.192 ;
     RECT  18.6 0.144 18.768 0.192 ;
     RECT  18.792 0.144 18.96 0.192 ;
     RECT  18.984 0.144 19.104 0.192 ;
     RECT  19.128 0.144 19.296 0.192 ;
     RECT  19.32 0.144 19.44 0.192 ;
     RECT  19.464 0.144 19.632 0.192 ;
     RECT  19.656 0.144 19.776 0.192 ;
     RECT  19.8 0.144 19.968 0.192 ;
     RECT  19.992 0.144 20.16 0.192 ;
     RECT  20.184 0.144 20.304 0.192 ;
     RECT  20.328 0.144 20.496 0.192 ;
     RECT  20.52 0.144 20.64 0.192 ;
     RECT  20.664 0.144 20.832 0.192 ;
     RECT  20.856 0.144 20.976 0.192 ;
     RECT  21 0.144 21.168 0.192 ;
     RECT  21.192 0.144 21.36 0.192 ;
     RECT  21.384 0.144 21.504 0.192 ;
     RECT  21.528 0.144 21.696 0.192 ;
     RECT  21.72 0.144 21.84 0.192 ;
     RECT  21.864 0.144 22.032 0.192 ;
     RECT  22.056 0.144 22.176 0.192 ;
     RECT  22.2 0.144 22.368 0.192 ;
     RECT  22.392 0.144 22.56 0.192 ;
     RECT  22.584 0.144 22.704 0.192 ;
     RECT  22.728 0.144 22.896 0.192 ;
     RECT  22.92 0.144 23.04 0.192 ;
     RECT  23.064 0.144 23.232 0.192 ;
     RECT  23.256 0.144 23.424 0.192 ;
     RECT  23.448 0.144 23.568 0.192 ;
     RECT  23.592 0.144 23.76 0.192 ;
     RECT  23.784 0.144 23.904 0.192 ;
     RECT  23.928 0.144 24.096 0.192 ;
     RECT  24.12 0.144 24.24 0.192 ;
     RECT  24.264 0.144 24.432 0.192 ;
     RECT  24.456 0.144 24.624 0.192 ;
     RECT  24.648 0.144 24.768 0.192 ;
     RECT  24.792 0.144 24.96 0.192 ;
     RECT  24.984 0.144 25.104 0.192 ;
     RECT  25.128 0.144 25.296 0.192 ;
     RECT  25.32 0.144 25.44 0.192 ;
     RECT  25.464 0.144 25.632 0.192 ;
     RECT  25.656 0.144 25.824 0.192 ;
     RECT  25.848 0.144 25.968 0.192 ;
     RECT  25.992 0.144 26.16 0.192 ;
     RECT  26.184 0.144 26.304 0.192 ;
     RECT  26.328 0.144 26.496 0.192 ;
     RECT  26.52 0.144 26.688 0.192 ;
     RECT  26.712 0.144 26.832 0.192 ;
     RECT  26.856 0.144 27.024 0.192 ;
     RECT  27.048 0.144 27.168 0.192 ;
     RECT  27.192 0.144 27.36 0.192 ;
     RECT  27.384 0.144 27.504 0.192 ;
     RECT  27.528 0.144 27.696 0.192 ;
     RECT  27.72 0.144 27.888 0.192 ;
     RECT  27.912 0.144 28.272 0.192 ;
     RECT  28.296 0.144 28.416 0.192 ;
     RECT  28.44 0.144 28.608 0.192 ;
     RECT  28.632 0.144 28.8 0.192 ;
     RECT  28.824 0.144 28.944 0.192 ;
     RECT  28.968 0.144 29.136 0.192 ;
     RECT  29.16 0.144 29.28 0.192 ;
     RECT  29.304 0.144 29.472 0.192 ;
     RECT  29.496 0.144 29.664 0.192 ;
     RECT  29.688 0.144 29.808 0.192 ;
     RECT  29.832 0.144 30 0.192 ;
     RECT  30.024 0.144 30.144 0.192 ;
     RECT  30.168 0.144 30.336 0.192 ;
     RECT  30.36 0.144 30.48 0.192 ;
     RECT  30.504 0.144 30.672 0.192 ;
     RECT  30.696 0.144 30.864 0.192 ;
     RECT  30.888 0.144 31.008 0.192 ;
     RECT  31.032 0.144 31.2 0.192 ;
     RECT  31.224 0.144 31.344 0.192 ;
     RECT  31.368 0.144 31.536 0.192 ;
     RECT  31.56 0.144 31.68 0.192 ;
     RECT  31.704 0.144 31.872 0.192 ;
     RECT  31.896 0.144 32.064 0.192 ;
     RECT  32.088 0.144 32.208 0.192 ;
     RECT  32.232 0.144 32.4 0.192 ;
     RECT  32.424 0.144 32.544 0.192 ;
     RECT  32.568 0.144 32.736 0.192 ;
     RECT  32.76 0.144 32.928 0.192 ;
     RECT  32.952 0.144 33.072 0.192 ;
     RECT  33.096 0.144 33.264 0.192 ;
     RECT  33.288 0.144 33.408 0.192 ;
     RECT  33.432 0.144 33.6 0.192 ;
     RECT  33.624 0.144 33.744 0.192 ;
     RECT  33.768 0.144 33.936 0.192 ;
     RECT  33.96 0.144 34.128 0.192 ;
     RECT  34.152 0.144 34.272 0.192 ;
     RECT  34.296 0.144 34.464 0.192 ;
     RECT  34.488 0.144 34.608 0.192 ;
     RECT  34.632 0.144 34.8 0.192 ;
     RECT  34.824 0.144 34.944 0.192 ;
     RECT  34.968 0.144 35.136 0.192 ;
     RECT  35.16 0.144 35.328 0.192 ;
     RECT  35.352 0.144 35.472 0.192 ;
     RECT  35.496 0.144 35.664 0.192 ;
     RECT  35.688 0.144 35.808 0.192 ;
     RECT  35.832 0.144 36 0.192 ;
     RECT  36.024 0.144 36.192 0.192 ;
     RECT  36.216 0.144 36.336 0.192 ;
     RECT  36.36 0.144 36.528 0.192 ;
     RECT  36.552 0.144 36.672 0.192 ;
     RECT  36.696 0.144 36.864 0.192 ;
     RECT  36.888 0.144 37.008 0.192 ;
     RECT  37.032 0.144 37.2 0.192 ;
     RECT  37.224 0.144 37.392 0.192 ;
     RECT  37.416 0.144 37.536 0.192 ;
     RECT  37.56 0.144 37.728 0.192 ;
     RECT  37.752 0.144 37.872 0.192 ;
     RECT  37.896 0.144 38.064 0.192 ;
     RECT  38.088 0.144 38.208 0.192 ;
     RECT  38.232 0.144 38.4 0.192 ;
     RECT  38.424 0.144 38.592 0.192 ;
     RECT  38.616 0.144 38.736 0.192 ;
     RECT  38.76 0.144 38.928 0.192 ;
     RECT  38.952 0.144 39.072 0.192 ;
     RECT  39.096 0.144 39.264 0.192 ;
     RECT  39.288 0.144 39.456 0.192 ;
     RECT  39.48 0.144 39.6 0.192 ;
     RECT  39.624 0.144 39.792 0.192 ;
     RECT  39.816 0.144 39.936 0.192 ;
     RECT  39.96 0.144 40.128 0.192 ;
     RECT  40.152 0.144 40.272 0.192 ;
     RECT  40.296 0.144 40.464 0.192 ;
     RECT  40.488 0.144 40.656 0.192 ;
     RECT  40.68 0.144 40.8 0.192 ;
     RECT  40.824 0.144 40.992 0.192 ;
     RECT  41.016 0.144 41.136 0.192 ;
     RECT  41.16 0.144 41.328 0.192 ;
     RECT  41.352 0.144 41.472 0.192 ;
     RECT  41.496 0.144 41.664 0.192 ;
     RECT  41.688 0.144 41.856 0.192 ;
     RECT  41.88 0.144 42 0.192 ;
     RECT  42.024 0.144 42.192 0.192 ;
     RECT  42.216 0.144 42.336 0.192 ;
     RECT  42.36 0.144 42.528 0.192 ;
     RECT  42.552 0.144 42.72 0.192 ;
     RECT  42.744 0.144 42.864 0.192 ;
     RECT  42.888 0.144 43.056 0.192 ;
     RECT  43.08 0.144 43.2 0.192 ;
     RECT  43.224 0.144 43.392 0.192 ;
     RECT  43.416 0.144 43.536 0.192 ;
     RECT  43.56 0.144 43.728 0.192 ;
     RECT  43.752 0.144 43.92 0.192 ;
     RECT  43.944 0.144 44.064 0.192 ;
     RECT  44.088 0.144 44.256 0.192 ;
     RECT  44.28 0.144 44.4 0.192 ;
     RECT  44.424 0.144 44.592 0.192 ;
     RECT  44.616 0.144 44.736 0.192 ;
     RECT  44.76 0.144 44.928 0.192 ;
     RECT  44.952 0.144 45.12 0.192 ;
     RECT  45.144 0.144 45.264 0.192 ;
     RECT  45.288 0.144 45.456 0.192 ;
     RECT  45.48 0.144 45.6 0.192 ;
     RECT  45.624 0.144 45.792 0.192 ;
     RECT  45.816 0.144 45.936 0.192 ;
     RECT  45.96 0.144 46.128 0.192 ;
     RECT  46.152 0.144 46.32 0.192 ;
     RECT  46.344 0.144 46.464 0.192 ;
     RECT  46.488 0.144 46.656 0.192 ;
     RECT  46.68 0.144 46.8 0.192 ;
     RECT  46.824 0.144 46.992 0.192 ;
     RECT  47.016 0.144 47.184 0.192 ;
     RECT  47.208 0.144 47.328 0.192 ;
     RECT  47.352 0.144 47.52 0.192 ;
     RECT  47.544 0.144 47.664 0.192 ;
     RECT  47.688 0.144 47.856 0.192 ;
     RECT  47.88 0.144 48 0.192 ;
     RECT  48.024 0.144 48.192 0.192 ;
     RECT  48.216 0.144 48.384 0.192 ;
     RECT  48.408 0.144 48.528 0.192 ;
     RECT  48.552 0.144 48.72 0.192 ;
     RECT  48.744 0.144 48.864 0.192 ;
     RECT  48.888 0.144 49.056 0.192 ;
     RECT  49.08 0.144 49.2 0.192 ;
     RECT  49.224 0.144 49.392 0.192 ;
     RECT  49.416 0.144 49.584 0.192 ;
     RECT  49.608 0.144 49.728 0.192 ;
     RECT  49.752 0.144 49.92 0.192 ;
     RECT  49.944 0.144 50.064 0.192 ;
     RECT  50.088 0.144 50.256 0.192 ;
     RECT  50.28 0.144 50.448 0.192 ;
     RECT  50.472 0.144 50.592 0.192 ;
     RECT  50.616 0.144 50.784 0.192 ;
     RECT  50.808 0.144 50.928 0.192 ;
     RECT  50.952 0.144 51.12 0.192 ;
     RECT  51.144 0.144 51.264 0.192 ;
     RECT  51.288 0.144 51.456 0.192 ;
     RECT  51.48 0.144 51.648 0.192 ;
     RECT  4.512 0.192 51.672 0.611 ;
     RECT  4.512 0.611 28.824 1.091 ;
     RECT  37.2 0.611 51.672 1.139 ;
     RECT  15.84 1.091 28.824 1.523 ;
     RECT  4.512 1.091 14.664 1.763 ;
     RECT  38.592 1.139 51.672 1.763 ;
     RECT  5.04 1.763 6.072 1.811 ;
     RECT  7.104 1.763 14.664 1.811 ;
     RECT  5.04 1.811 5.592 2.051 ;
     RECT  23.232 1.523 28.824 2.137 ;
     RECT  29.808 0.611 36.216 2.137 ;
     RECT  37.392 1.139 37.56 2.137 ;
     RECT  15.84 1.523 21.72 2.149 ;
     RECT  2.4 2.137 2.52 2.151 ;
     RECT  37.392 2.137 37.62 2.151 ;
     RECT  38.592 1.763 41.016 2.151 ;
     RECT  53.7 2.137 53.82 2.151 ;
     RECT  37.392 2.151 41.016 2.195 ;
     RECT  7.104 1.811 13.656 2.243 ;
     RECT  7.104 2.243 13.608 2.291 ;
     RECT  15.792 2.149 21.72 2.291 ;
     RECT  39.072 2.195 41.016 2.291 ;
     RECT  42.72 1.763 49.416 2.291 ;
     RECT  13.2 2.291 13.608 2.339 ;
     RECT  23.232 2.137 36.216 2.675 ;
     RECT  23.232 2.675 28.104 2.819 ;
     RECT  37.392 2.195 37.812 2.867 ;
     RECT  39.072 2.291 40.68 2.867 ;
     RECT  42.9 2.291 49.416 2.867 ;
     RECT  7.104 2.291 11.928 2.915 ;
     RECT  42.9 2.867 43.416 2.915 ;
     RECT  44.4 2.867 47.016 2.915 ;
     RECT  51 1.763 51.672 2.915 ;
     RECT  29.4 2.675 36.216 3.107 ;
     RECT  15.9 2.291 21.72 3.155 ;
     RECT  14.64 1.811 14.664 3.347 ;
     RECT  25.296 2.819 28.104 3.443 ;
     RECT  39.072 2.867 39.096 3.443 ;
     RECT  42.9 2.915 43.32 3.443 ;
     RECT  44.736 2.915 45.912 3.443 ;
     RECT  46.992 2.915 47.016 3.443 ;
     RECT  15.9 3.155 18.912 3.683 ;
     RECT  25.824 3.443 27.012 3.683 ;
     RECT  29.4 3.107 30.504 3.731 ;
     RECT  31.536 3.107 36.216 4.019 ;
     RECT  26.304 3.683 27.012 4.163 ;
     RECT  34.8 4.019 36.216 4.163 ;
     RECT  40.2 2.867 40.68 4.211 ;
     RECT  20.16 3.155 21.72 4.739 ;
     RECT  31.536 4.019 33.288 4.787 ;
     RECT  15.9 3.683 17.592 4.979 ;
     RECT  36.192 4.163 36.216 5.027 ;
     RECT  5.1 2.051 5.592 5.171 ;
     RECT  7.8 2.915 11.928 5.171 ;
     RECT  9.84 5.171 11.928 5.219 ;
     RECT  10.368 5.219 11.928 5.507 ;
     RECT  31.536 4.787 32.412 5.555 ;
     RECT  10.5 5.507 11.928 5.603 ;
     RECT  15.9 4.979 16.92 5.603 ;
     RECT  7.8 5.171 8.472 5.747 ;
     RECT  11.904 5.603 11.928 5.747 ;
     RECT  48.3 2.867 49.416 5.747 ;
     RECT  23.232 2.819 24.312 6.611 ;
     RECT  20.976 4.739 21.72 6.947 ;
     RECT  23.904 6.611 24.312 7.187 ;
     RECT  21.3 6.947 21.72 7.907 ;
     RECT  5.1 5.171 5.412 15.349 ;
     RECT  4.128 15.349 5.412 16.019 ;
     RECT  34.8 4.163 35.112 16.261 ;
     RECT  13.2 2.339 13.512 16.357 ;
     RECT  21.3 7.907 21.612 16.357 ;
     RECT  29.4 3.731 29.712 16.357 ;
     RECT  42.9 3.443 43.212 16.357 ;
     RECT  45.6 3.443 45.912 16.357 ;
     RECT  10.5 5.603 10.812 16.501 ;
     RECT  34.416 16.261 35.112 16.501 ;
     RECT  13.2 16.357 13.608 16.547 ;
     RECT  21.3 16.357 21.72 16.547 ;
     RECT  29.4 16.357 29.832 16.547 ;
     RECT  7.8 5.747 8.112 16.741 ;
     RECT  21.3 16.547 21.612 16.837 ;
     RECT  32.1 5.555 32.412 16.885 ;
     RECT  51 2.915 51.312 16.933 ;
     RECT  18.6 3.683 18.912 17.029 ;
     RECT  21.024 16.837 21.612 17.029 ;
     RECT  48.3 5.747 48.612 17.029 ;
     RECT  40.2 4.211 40.512 17.077 ;
     RECT  42.9 16.357 43.368 17.077 ;
     RECT  45.504 16.357 45.912 17.077 ;
     RECT  7.8 16.741 8.52 17.459 ;
     RECT  45.12 17.077 45.912 17.461 ;
     RECT  32.1 16.885 33.096 17.605 ;
     RECT  42.9 17.077 43.56 17.893 ;
     RECT  31.968 17.605 33.096 17.987 ;
     RECT  10.272 16.501 10.812 18.035 ;
     RECT  31.968 17.987 32.412 18.035 ;
     RECT  24 7.187 24.312 18.181 ;
     RECT  47.712 17.029 48.612 18.275 ;
     RECT  18.6 17.029 21.612 18.805 ;
     RECT  24 18.181 24.408 18.805 ;
     RECT  23.568 18.805 24.408 18.901 ;
     RECT  25.632 18.853 25.656 18.901 ;
     RECT  5.1 16.019 5.412 19.333 ;
     RECT  6.576 18.805 6.6 19.333 ;
     RECT  7.8 17.459 8.112 19.333 ;
     RECT  10.5 18.035 10.812 19.333 ;
     RECT  11.808 16.357 11.832 19.333 ;
     RECT  13.2 16.547 13.512 19.333 ;
     RECT  15.9 5.603 16.212 19.333 ;
     RECT  18.6 18.805 21.864 19.333 ;
     RECT  23.568 18.901 25.656 19.333 ;
     RECT  26.7 4.163 27.012 19.333 ;
     RECT  28.08 3.443 28.104 19.333 ;
     RECT  29.4 16.547 29.712 19.333 ;
     RECT  32.1 18.035 32.412 19.333 ;
     RECT  34.416 16.501 35.88 19.333 ;
     RECT  37.5 2.867 37.812 19.333 ;
     RECT  38.832 18.901 38.856 19.333 ;
     RECT  40.2 17.077 40.824 19.333 ;
     RECT  42.9 17.893 43.8 19.333 ;
     RECT  45.12 17.461 46.728 19.333 ;
     RECT  47.904 18.275 48.612 19.333 ;
     RECT  50.88 16.933 51.312 19.333 ;
     RECT  2.4 2.151 2.712 19.449 ;
     RECT  53.7 2.151 54.012 19.449 ;
     RECT  2.4 19.449 2.52 19.463 ;
     RECT  53.7 19.449 53.82 19.463 ;
     RECT  4.512 19.333 51.672 21.408 ;
     RECT  4.536 21.408 4.848 21.456 ;
     RECT  4.872 21.408 5.184 21.456 ;
     RECT  5.208 21.408 5.568 21.456 ;
     RECT  5.592 21.408 5.904 21.456 ;
     RECT  5.928 21.408 6.24 21.456 ;
     RECT  6.264 21.408 6.576 21.456 ;
     RECT  6.6 21.408 6.912 21.456 ;
     RECT  6.936 21.408 7.296 21.456 ;
     RECT  7.32 21.408 7.632 21.456 ;
     RECT  7.656 21.408 7.968 21.456 ;
     RECT  7.992 21.408 8.304 21.456 ;
     RECT  8.328 21.408 8.688 21.456 ;
     RECT  8.712 21.408 9.024 21.456 ;
     RECT  9.048 21.408 9.36 21.456 ;
     RECT  9.384 21.408 9.696 21.456 ;
     RECT  9.72 21.408 10.032 21.456 ;
     RECT  10.056 21.408 10.416 21.456 ;
     RECT  10.44 21.408 10.752 21.456 ;
     RECT  10.776 21.408 11.088 21.456 ;
     RECT  11.112 21.408 11.424 21.456 ;
     RECT  11.448 21.408 11.76 21.456 ;
     RECT  11.784 21.408 12.144 21.456 ;
     RECT  12.168 21.408 12.48 21.456 ;
     RECT  12.504 21.408 12.816 21.456 ;
     RECT  12.84 21.408 13.152 21.456 ;
     RECT  13.176 21.408 13.536 21.456 ;
     RECT  13.56 21.408 13.872 21.456 ;
     RECT  13.896 21.408 14.208 21.456 ;
     RECT  14.232 21.408 14.544 21.456 ;
     RECT  14.568 21.408 14.88 21.456 ;
     RECT  14.904 21.408 15.264 21.456 ;
     RECT  15.288 21.408 15.6 21.456 ;
     RECT  15.624 21.408 15.936 21.456 ;
     RECT  15.96 21.408 16.272 21.456 ;
     RECT  16.296 21.408 16.656 21.456 ;
     RECT  16.68 21.408 16.992 21.456 ;
     RECT  17.016 21.408 17.328 21.456 ;
     RECT  17.352 21.408 17.664 21.456 ;
     RECT  17.688 21.408 18 21.456 ;
     RECT  18.024 21.408 18.384 21.456 ;
     RECT  18.408 21.408 18.72 21.456 ;
     RECT  18.744 21.408 19.056 21.456 ;
     RECT  19.08 21.408 19.392 21.456 ;
     RECT  19.416 21.408 19.776 21.456 ;
     RECT  19.8 21.408 20.112 21.456 ;
     RECT  20.136 21.408 20.448 21.456 ;
     RECT  20.472 21.408 20.784 21.456 ;
     RECT  20.808 21.408 21.12 21.456 ;
     RECT  21.144 21.408 21.504 21.456 ;
     RECT  21.528 21.408 21.84 21.456 ;
     RECT  21.864 21.408 22.176 21.456 ;
     RECT  22.2 21.408 22.512 21.456 ;
     RECT  22.536 21.408 22.848 21.456 ;
     RECT  22.872 21.408 23.232 21.456 ;
     RECT  23.256 21.408 23.568 21.456 ;
     RECT  23.592 21.408 23.904 21.456 ;
     RECT  23.928 21.408 24.24 21.456 ;
     RECT  24.264 21.408 24.624 21.456 ;
     RECT  24.648 21.408 24.96 21.456 ;
     RECT  24.984 21.408 25.296 21.456 ;
     RECT  25.32 21.408 25.632 21.456 ;
     RECT  25.656 21.408 25.968 21.456 ;
     RECT  25.992 21.408 26.352 21.456 ;
     RECT  26.376 21.408 26.688 21.456 ;
     RECT  26.712 21.408 27.024 21.456 ;
     RECT  27.048 21.408 27.36 21.456 ;
     RECT  27.384 21.408 27.744 21.456 ;
     RECT  27.768 21.408 28.08 21.456 ;
     RECT  28.104 21.408 28.416 21.456 ;
     RECT  28.44 21.408 28.752 21.456 ;
     RECT  28.776 21.408 29.088 21.456 ;
     RECT  29.112 21.408 29.472 21.456 ;
     RECT  29.496 21.408 29.808 21.456 ;
     RECT  29.832 21.408 30.144 21.456 ;
     RECT  30.168 21.408 30.48 21.456 ;
     RECT  30.504 21.408 30.816 21.456 ;
     RECT  30.84 21.408 31.2 21.456 ;
     RECT  31.224 21.408 31.536 21.456 ;
     RECT  31.56 21.408 31.872 21.456 ;
     RECT  31.896 21.408 32.208 21.456 ;
     RECT  32.232 21.408 32.592 21.456 ;
     RECT  32.616 21.408 32.928 21.456 ;
     RECT  32.952 21.408 33.264 21.456 ;
     RECT  33.288 21.408 33.6 21.456 ;
     RECT  33.624 21.408 33.936 21.456 ;
     RECT  33.96 21.408 34.32 21.456 ;
     RECT  34.344 21.408 34.656 21.456 ;
     RECT  34.68 21.408 34.992 21.456 ;
     RECT  35.016 21.408 35.328 21.456 ;
     RECT  35.352 21.408 35.712 21.456 ;
     RECT  35.736 21.408 36.048 21.456 ;
     RECT  36.072 21.408 36.384 21.456 ;
     RECT  36.408 21.408 36.72 21.456 ;
     RECT  36.744 21.408 37.056 21.456 ;
     RECT  37.08 21.408 37.44 21.456 ;
     RECT  37.464 21.408 37.776 21.456 ;
     RECT  37.8 21.408 38.112 21.456 ;
     RECT  38.136 21.408 38.448 21.456 ;
     RECT  38.472 21.408 38.832 21.456 ;
     RECT  38.856 21.408 39.168 21.456 ;
     RECT  39.192 21.408 39.504 21.456 ;
     RECT  39.528 21.408 39.84 21.456 ;
     RECT  39.864 21.408 40.176 21.456 ;
     RECT  40.2 21.408 40.56 21.456 ;
     RECT  40.584 21.408 40.896 21.456 ;
     RECT  40.92 21.408 41.232 21.456 ;
     RECT  41.256 21.408 41.568 21.456 ;
     RECT  41.592 21.408 41.904 21.456 ;
     RECT  41.928 21.408 42.288 21.456 ;
     RECT  42.312 21.408 42.624 21.456 ;
     RECT  42.648 21.408 42.96 21.456 ;
     RECT  42.984 21.408 43.296 21.456 ;
     RECT  43.32 21.408 43.68 21.456 ;
     RECT  43.704 21.408 44.016 21.456 ;
     RECT  44.04 21.408 44.352 21.456 ;
     RECT  44.376 21.408 44.688 21.456 ;
     RECT  44.712 21.408 45.024 21.456 ;
     RECT  45.048 21.408 45.408 21.456 ;
     RECT  45.432 21.408 45.744 21.456 ;
     RECT  45.768 21.408 46.08 21.456 ;
     RECT  46.104 21.408 46.416 21.456 ;
     RECT  46.44 21.408 46.8 21.456 ;
     RECT  46.824 21.408 47.136 21.456 ;
     RECT  47.16 21.408 47.472 21.456 ;
     RECT  47.496 21.408 47.808 21.456 ;
     RECT  47.832 21.408 48.144 21.456 ;
     RECT  48.168 21.408 48.528 21.456 ;
     RECT  48.552 21.408 48.864 21.456 ;
     RECT  48.888 21.408 49.2 21.456 ;
     RECT  49.224 21.408 49.536 21.456 ;
     RECT  49.56 21.408 49.872 21.456 ;
     RECT  49.896 21.408 50.256 21.456 ;
     RECT  50.28 21.408 50.592 21.456 ;
     RECT  50.616 21.408 50.928 21.456 ;
     RECT  50.952 21.408 51.264 21.456 ;
     RECT  51.288 21.408 51.648 21.456 ;
     RECT  28.824 0.611 29.808 2.137 ;
     RECT  36.216 0.611 37.2 1.139 ;
     RECT  14.664 1.091 15.84 2.149 ;
     RECT  36.216 1.139 37.392 2.867 ;
     RECT  37.56 1.139 38.592 2.137 ;
     RECT  21.72 1.523 23.232 6.611 ;
     RECT  6.072 1.763 7.104 1.811 ;
     RECT  5.592 1.811 7.104 2.915 ;
     RECT  13.656 1.811 14.64 2.243 ;
     RECT  37.62 2.137 38.592 2.151 ;
     RECT  14.664 2.149 15.792 2.291 ;
     RECT  37.812 2.195 39.072 3.443 ;
     RECT  13.608 2.243 14.64 2.339 ;
     RECT  11.928 2.291 13.2 5.747 ;
     RECT  14.664 2.291 15.9 3.347 ;
     RECT  13.512 2.339 14.64 3.347 ;
     RECT  28.104 2.675 29.4 19.333 ;
     RECT  24.312 2.819 25.296 3.443 ;
     RECT  36.216 2.867 37.5 5.027 ;
     RECT  39.096 2.867 40.2 3.443 ;
     RECT  43.416 2.867 44.4 2.915 ;
     RECT  47.016 2.867 48.3 3.443 ;
     RECT  43.32 2.915 44.736 3.443 ;
     RECT  45.912 2.915 46.992 3.443 ;
     RECT  30.504 3.107 31.536 3.731 ;
     RECT  18.912 3.155 20.16 4.739 ;
     RECT  24.312 3.443 25.824 3.683 ;
     RECT  27.012 3.443 28.08 19.333 ;
     RECT  17.592 3.683 18.6 4.979 ;
     RECT  33.288 4.019 34.8 4.787 ;
     RECT  35.112 4.163 36.192 5.027 ;
     RECT  8.472 5.171 9.84 5.219 ;
     RECT  10.812 5.603 11.904 5.747 ;
     RECT  2.712 15.349 4.128 16.019 ;
     RECT  10.812 16.357 11.808 19.333 ;
     RECT  11.832 16.357 13.2 19.333 ;
     RECT  33.096 16.885 34.416 17.987 ;
     RECT  46.728 17.461 47.712 18.275 ;
     RECT  43.8 17.893 45.12 19.333 ;
     RECT  32.412 17.987 34.416 19.333 ;
     RECT  10.272 18.035 10.5 19.333 ;
     RECT  31.968 18.035 32.1 19.333 ;
     RECT  46.728 18.275 47.904 19.333 ;
     RECT  5.412 18.805 6.576 19.333 ;
     RECT  6.6 18.805 7.8 19.333 ;
     RECT  24.408 18.853 25.632 18.901 ;
     RECT  25.656 18.853 26.7 19.333 ;
     RECT  37.812 18.901 38.832 19.333 ;
     RECT  38.856 18.901 40.2 19.333 ;
  END
END hbfd_rly_136_NS_fc_f2
END LIBRARY
